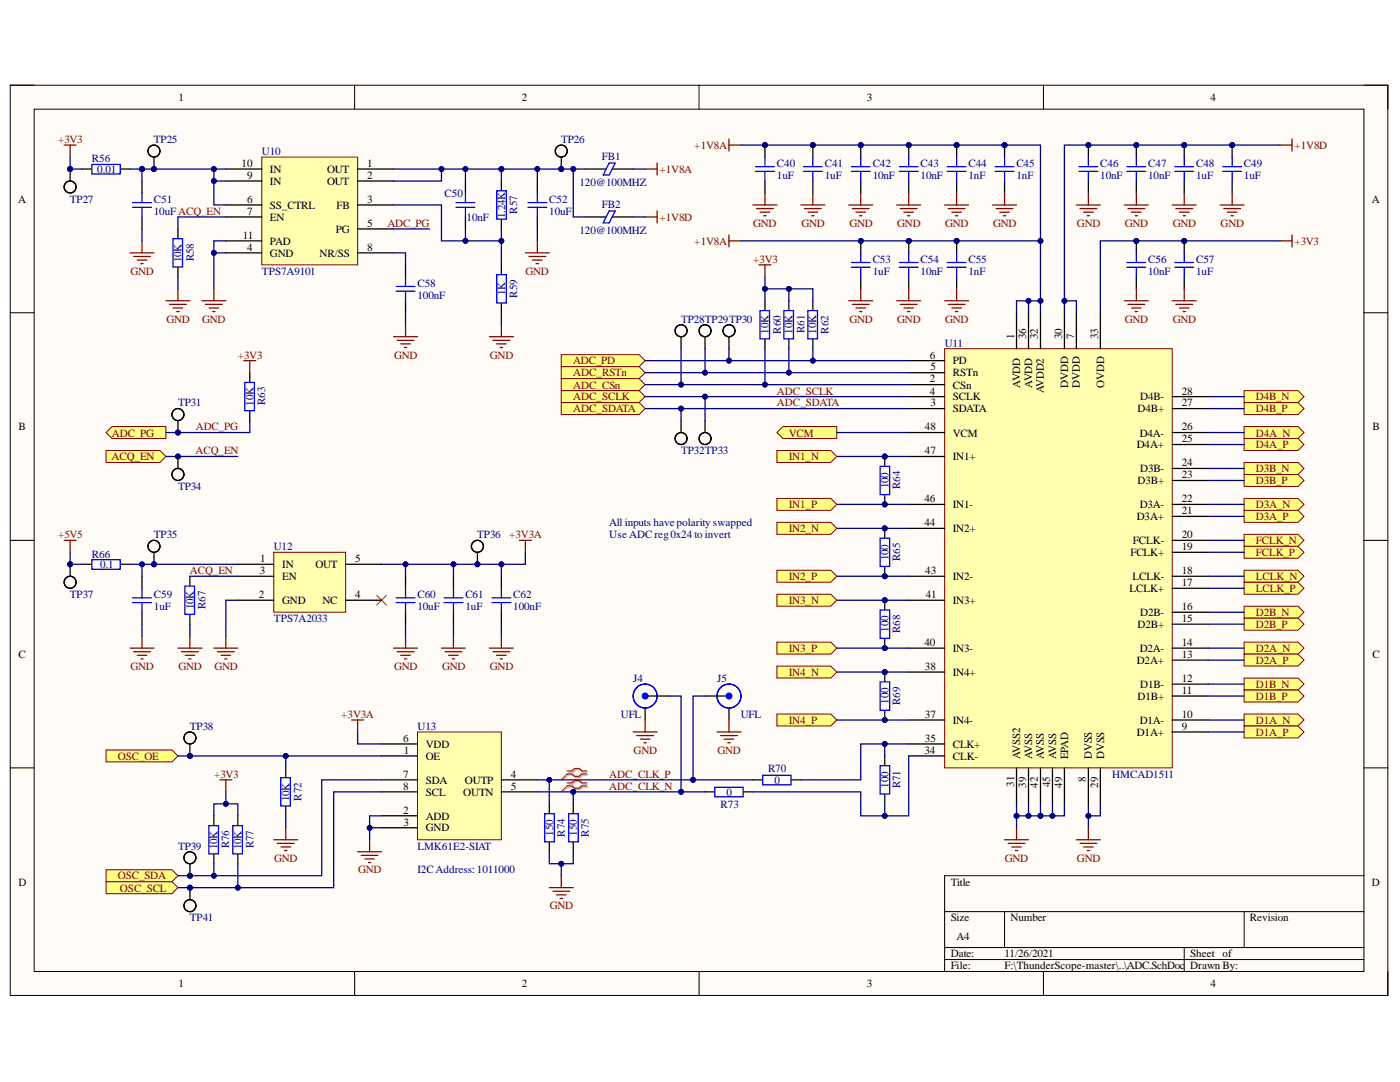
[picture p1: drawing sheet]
<svg xmlns="http://www.w3.org/2000/svg" width="279mm" height="216mm" viewBox="0 0 279 216" stroke-linecap="round" stroke-linejoin="round" font-family="sans-serif">
<defs><g id="words">
<g font-size="2.2">
<text x="35.6" y="20.1">1</text>
<text x="104.1" y="20.1">2</text>
<text x="173" y="20.1">3</text>
<text x="241.6" y="20.1">4</text>
<text x="48.2" y="33.3">10</text>
<text x="49.3" y="35.7">9</text>
<text x="53.9" y="34.5">IN</text>
<text x="65.3" y="34.5">OUT</text>
<text x="73.3" y="33.3">1</text>
<text x="73.3" y="35.7">2</text>
<text x="3.6" y="40.4">A</text>
<text x="49.3" y="40.4">6</text>
<text x="53.9" y="41.7">SS_CTRL</text>
<text x="53.9" y="36.9">IN</text>
<text x="65.3" y="36.9">OUT</text>
<text x="67.2" y="41.7">FB</text>
<text x="73.3" y="40.4">3</text>
<text x="273.8" y="40.4">A</text>
<text x="48.5" y="47.6">11</text>
<text x="49.3" y="42.9">7</text>
<text x="53.9" y="44.1">EN</text>
<text x="67" y="46.4">PG</text>
<text x="73.3" y="45.2">5</text>
<text x="49.3" y="50.1">4</text>
<text x="53.9" y="51.2">GND</text>
<text x="53.9" y="48.8">PAD</text>
<text x="63.8" y="51.2">NR/SS</text>
<text x="73.3" y="50.1">8</text>
<text x="185.6" y="71.5">6</text>
<text x="202.4" y="67.7" transform="rotate(-90 202.4 67.7)">1</text>
<text x="204.8" y="67.7" transform="rotate(-90 204.8 67.7)">36</text>
<text x="207.2" y="67.7" transform="rotate(-90 207.2 67.7)">32</text>
<text x="212" y="67.7" transform="rotate(-90 212 67.7)">30</text>
<text x="214.3" y="67.7" transform="rotate(-90 214.3 67.7)">7</text>
<text x="219.2" y="67.7" transform="rotate(-90 219.2 67.7)">33</text>
<text x="185.6" y="76.3">2</text>
<text x="185.7" y="73.9">5</text>
<text x="190.2" y="72.7">PD</text>
<text x="190.2" y="75.1">RSTn</text>
<text x="190.2" y="77.5">CSn</text>
<text x="203.6" y="77.4" transform="rotate(-90 203.6 77.4)">AVDD</text>
<text x="206" y="77.4" transform="rotate(-90 206 77.4)">AVDD</text>
<text x="213.2" y="77.4" transform="rotate(-90 213.2 77.4)">DVDD</text>
<text x="215.5" y="77.4" transform="rotate(-90 215.5 77.4)">DVDD</text>
<text x="220.3" y="77.4" transform="rotate(-90 220.3 77.4)">OVDD</text>
<text x="185.6" y="78.7">4</text>
<text x="185.7" y="81.1">3</text>
<text x="190.2" y="79.9">SCLK</text>
<text x="190.2" y="82.3">SDATA</text>
<text x="208.3" y="78.5" transform="rotate(-90 208.3 78.5)">AVDD2</text>
<text x="227" y="82.3">D4B+</text>
<text x="227.5" y="79.9">D4B-</text>
<text x="235.8" y="81.1">27</text>
<text x="235.8" y="78.7">28</text>
<text x="3.7" y="85.8">B</text>
<text x="184.6" y="85.8">48</text>
<text x="190.2" y="87.1">VCM</text>
<text x="226.9" y="89.5">D4A+</text>
<text x="227.5" y="87.1">D4A-</text>
<text x="235.8" y="88.3">25</text>
<text x="235.8" y="85.8">26</text>
<text x="273.9" y="85.8">B</text>
<text x="184.6" y="90.7">47</text>
<text x="190.2" y="91.8">IN1+</text>
<text x="227.5" y="94.2">D3B-</text>
<text x="235.8" y="95.5">23</text>
<text x="235.8" y="93">24</text>
<text x="184.5" y="100.2">46</text>
<text x="190.2" y="101.4">IN1-</text>
<text x="227" y="96.7">D3B+</text>
<text x="227.5" y="101.4">D3A-</text>
<text x="235.8" y="100.2">22</text>
<text x="184.5" y="105">44</text>
<text x="190.2" y="106.2">IN2+</text>
<text x="226.9" y="103.8">D3A+</text>
<text x="235.8" y="107.4">20</text>
<text x="235.8" y="102.6">21</text>
<text x="51.9" y="112.1">1</text>
<text x="56.3" y="113.4">IN</text>
<text x="62.9" y="113.4">OUT</text>
<text x="70.9" y="112.1">5</text>
<text x="225.6" y="110.9">FCLK+</text>
<text x="226.1" y="108.6">FCLK-</text>
<text x="235.8" y="109.8">19</text>
<text x="51.7" y="119.3">2</text>
<text x="51.9" y="114.6">3</text>
<text x="56.3" y="115.8">EN</text>
<text x="70.9" y="119.3">4</text>
<text x="184.7" y="114.6">43</text>
<text x="184.7" y="119.3">41</text>
<text x="190.2" y="115.8">IN2-</text>
<text x="225.4" y="118.1">LCLK+</text>
<text x="226" y="115.8">LCLK-</text>
<text x="235.8" y="116.9">17</text>
<text x="235.8" y="114.6">18</text>
<text x="56.3" y="120.5">GND</text>
<text x="64.4" y="120.5">NC</text>
<text x="190.2" y="120.5">IN3+</text>
<text x="227" y="125.3">D2B+</text>
<text x="227.5" y="123">D2B-</text>
<text x="235.8" y="124.1">15</text>
<text x="235.8" y="121.7">16</text>
<text x="3.7" y="131.3">C</text>
<text x="184.5" y="128.9">40</text>
<text x="190.2" y="130.1">IN3-</text>
<text x="227.5" y="130.1">D2A-</text>
<text x="235.8" y="131.3">13</text>
<text x="235.8" y="128.9">14</text>
<text x="273.9" y="131.3">C</text>
<text x="184.6" y="133.7">38</text>
<text x="190.2" y="134.9">IN4+</text>
<text x="226.9" y="132.5">D2A+</text>
<text x="227.5" y="137.2">D1B-</text>
<text x="235.8" y="136.1">12</text>
<text x="184.6" y="143.2">37</text>
<text x="227" y="139.6">D1B+</text>
<text x="235.8" y="143.2">10</text>
<text x="235.8" y="138.4">11</text>
<text x="80.4" y="148">6</text>
<text x="85" y="149.2">VDD</text>
<text x="184.6" y="148">35</text>
<text x="190.2" y="144.4">IN4-</text>
<text x="190.2" y="149.2">CLK+</text>
<text x="226.9" y="146.8">D1A+</text>
<text x="227.5" y="144.4">D1A-</text>
<text x="235.8" y="145.6">9</text>
<text x="80.4" y="155.2">7</text>
<text x="80.6" y="150.4">1</text>
<text x="85" y="151.6">OE</text>
<text x="101.9" y="155.2">4</text>
<text x="184.5" y="150.4">34</text>
<text x="190.2" y="151.6">CLK-</text>
<text x="203.6" y="151.5" transform="rotate(-90 203.6 151.5)">AVSS2</text>
<text x="206" y="151.5" transform="rotate(-90 206 151.5)">AVSS</text>
<text x="208.3" y="151.5" transform="rotate(-90 208.3 151.5)">AVSS</text>
<text x="210.8" y="151.5" transform="rotate(-90 210.8 151.5)">AVSS</text>
<text x="213.2" y="151.5" transform="rotate(-90 213.2 151.5)">EPAD</text>
<text x="217.9" y="151.5" transform="rotate(-90 217.9 151.5)">DVSS</text>
<text x="220.3" y="151.5" transform="rotate(-90 220.3 151.5)">DVSS</text>
<text x="80.4" y="157.5">8</text>
<text x="85" y="156.4">SDA</text>
<text x="85" y="158.8">SCL</text>
<text x="92.5" y="158.8">OUTN</text>
<text x="92.8" y="156.4">OUTP</text>
<text x="101.9" y="157.5">5</text>
<text x="202.4" y="157" transform="rotate(-90 202.4 157)">31</text>
<text x="204.8" y="157.2" transform="rotate(-90 204.8 157.2)">39</text>
<text x="207.2" y="157.2" transform="rotate(-90 207.2 157.2)">42</text>
<text x="209.6" y="157.1" transform="rotate(-90 209.6 157.1)">45</text>
<text x="212" y="157.2" transform="rotate(-90 212 157.2)">49</text>
<text x="216.7" y="156.1" transform="rotate(-90 216.7 156.1)">8</text>
<text x="219.2" y="157.2" transform="rotate(-90 219.2 157.2)">29</text>
<text x="80.4" y="162.4">2</text>
<text x="80.5" y="164.7">3</text>
<text x="85" y="163.5">ADD</text>
<text x="85" y="165.9">GND</text>
<text x="3.7" y="176.7">D</text>
<text x="189.7" y="176.7">Title</text>
<text x="273.8" y="176.7">D</text>
<text x="189.7" y="183.8">Size</text>
<text x="201.7" y="183.8">Number</text>
<text x="249.4" y="183.8">Revision</text>
<text x="189.7" y="191">Date:</text>
<text x="190.9" y="187.5">A4</text>
<text x="200.5" y="191">11/26/2021</text>
<text x="237.5" y="191">Sheet of</text>
<text x="35.6" y="197">1</text>
<text x="104.1" y="197">2</text>
<text x="173" y="197">3</text>
<text x="189.7" y="193.4">File:</text>
<text x="200.5" y="193.4">F:\ThunderScope-master\..\ADC.SchDoc</text>
<text x="237.5" y="193.4">Drawn By:</text>
<text x="241.6" y="197">4</text>
</g>
<g font-size="2.2" fill="#800000">
<text x="11.6" y="28.5">+3V3</text>
<text x="138.6" y="29.7">+1V8A</text>
<text x="258.3" y="29.7">+1V8D</text>
<text x="131.6" y="34.5">+1V8A</text>
<text x="77.3" y="45.2">ADC_PG</text>
<text x="131.6" y="44.1">+1V8D</text>
<text x="150.3" y="45.2">GND</text>
<text x="160" y="45.2">GND</text>
<text x="169.5" y="45.2">GND</text>
<text x="179.1" y="45.2">GND</text>
<text x="188.6" y="45.2">GND</text>
<text x="198.2" y="45.2">GND</text>
<text x="214.9" y="45.2">GND</text>
<text x="224.5" y="45.2">GND</text>
<text x="234.1" y="45.2">GND</text>
<text x="243.6" y="45.2">GND</text>
<text x="138.6" y="48.8">+1V8A</text>
<text x="150.3" y="52.4">+3V3</text>
<text x="258.3" y="48.8">+3V3</text>
<text x="26.1" y="54.8">GND</text>
<text x="104.9" y="54.8">GND</text>
<text x="33.2" y="64.4">GND</text>
<text x="40.3" y="64.4">GND</text>
<text x="169.5" y="64.4">GND</text>
<text x="179.1" y="64.4">GND</text>
<text x="188.6" y="64.4">GND</text>
<text x="224.5" y="64.4">GND</text>
<text x="234.1" y="64.4">GND</text>
<text x="47.5" y="71.5">+3V3</text>
<text x="78.7" y="71.5">GND</text>
<text x="97.8" y="71.5">GND</text>
<text x="114.4" y="72.7">ADC_PD</text>
<text x="114.4" y="75.1">ADC_RSTn</text>
<text x="114.4" y="77.5">ADC_CSn</text>
<text x="114.4" y="79.9">ADC_SCLK</text>
<text x="114.4" y="82.3">ADC_SDATA</text>
<text x="155" y="78.7">ADC_SCLK</text>
<text x="155" y="81.1">ADC_SDATA</text>
<text x="250.6" y="79.9">D4B_N</text>
<text x="250.6" y="82.3">D4B_P</text>
<text x="22.3" y="87.1">ADC_PG</text>
<text x="39.1" y="85.8">ADC_PG</text>
<text x="157.4" y="87.1">VCM</text>
<text x="250.6" y="87.1">D4A_N</text>
<text x="250.6" y="89.5">D4A_P</text>
<text x="22.2" y="91.8">ACQ_EN</text>
<text x="39" y="90.7">ACQ_EN</text>
<text x="157.4" y="91.8">IN1_N</text>
<text x="250.6" y="94.2">D3B_N</text>
<text x="157.4" y="101.4">IN1_P</text>
<text x="250.6" y="96.7">D3B_P</text>
<text x="250.6" y="101.4">D3A_N</text>
<text x="11.6" y="107.4">+5V5</text>
<text x="101.6" y="107.4">+3V3A</text>
<text x="157.4" y="106.2">IN2_N</text>
<text x="250.6" y="103.8">D3A_P</text>
<text x="250.6" y="108.6">FCLK_N</text>
<text x="250.6" y="110.9">FCLK_P</text>
<text x="37.9" y="114.6">ACQ_EN</text>
<text x="157.4" y="115.8">IN2_P</text>
<text x="250.6" y="115.8">LCLK_N</text>
<text x="250.6" y="118.1">LCLK_P</text>
<text x="157.4" y="120.5">IN3_N</text>
<text x="250.6" y="123">D2B_N</text>
<text x="250.6" y="125.3">D2B_P</text>
<text x="157.4" y="130.1">IN3_P</text>
<text x="250.6" y="130.1">D2A_N</text>
<text x="26.1" y="133.7">GND</text>
<text x="35.6" y="133.7">GND</text>
<text x="42.8" y="133.7">GND</text>
<text x="78.7" y="133.7">GND</text>
<text x="88.2" y="133.7">GND</text>
<text x="97.8" y="133.7">GND</text>
<text x="157.4" y="134.9">IN4_N</text>
<text x="250.6" y="132.5">D2A_P</text>
<text x="250.6" y="137.2">D1B_N</text>
<text x="68.1" y="143.2">+3V3A</text>
<text x="250.6" y="139.6">D1B_P</text>
<text x="157.4" y="144.4">IN4_P</text>
<text x="250.6" y="144.4">D1A_N</text>
<text x="250.6" y="146.8">D1A_P</text>
<text x="23.5" y="151.6">OSC_OE</text>
<text x="42.7" y="155.2">+3V3</text>
<text x="121.6" y="155.2">ADC_CLK_P</text>
<text x="126.5" y="150.4">GND</text>
<text x="143.2" y="150.4">GND</text>
<text x="121.6" y="157.5">ADC_CLK_N</text>
<text x="54.7" y="171.9">GND</text>
<text x="200.6" y="171.9">GND</text>
<text x="214.9" y="171.9">GND</text>
<text x="23.5" y="175.5">OSC_SDA</text>
<text x="23.9" y="177.9">OSC_SCL</text>
<text x="71.5" y="174.3">GND</text>
<text x="109.7" y="181.5">GND</text>
</g>
<g font-size="2.2" fill="#000080">
<text x="30.7" y="28.5">TP25</text>
<text x="112" y="28.5">TP26</text>
<text x="18.4" y="32.4">R56</text>
<text x="19.4" y="34.5">0.01</text>
<text x="52.3" y="30.9">U10</text>
<text x="120.1" y="31.9">FB1</text>
<text x="155" y="33.3">C40</text>
<text x="155" y="35.7">1uF</text>
<text x="164.6" y="33.3">C41</text>
<text x="164.6" y="35.7">1uF</text>
<text x="174.2" y="33.3">C42</text>
<text x="174.2" y="35.7">10nF</text>
<text x="183.7" y="33.3">C43</text>
<text x="183.7" y="35.7">10nF</text>
<text x="193.3" y="33.3">C44</text>
<text x="193.3" y="35.7">1nF</text>
<text x="202.8" y="33.3">C45</text>
<text x="202.8" y="35.7">1nF</text>
<text x="219.6" y="33.3">C46</text>
<text x="219.6" y="35.7">10nF</text>
<text x="229.1" y="33.3">C47</text>
<text x="229.1" y="35.7">10nF</text>
<text x="238.7" y="33.3">C48</text>
<text x="238.7" y="35.7">1uF</text>
<text x="248.3" y="33.3">C49</text>
<text x="248.3" y="35.7">1uF</text>
<text x="14" y="40.4">TP27</text>
<text x="30.7" y="40.4">C51</text>
<text x="88.7" y="39.2">C50</text>
<text x="109.6" y="40.4">C52</text>
<text x="115.6" y="37.1">120@100MHZ</text>
<text x="120.1" y="41.4">FB2</text>
<text x="30.7" y="42.9">10uFACQ_EN</text>
<text x="93.1" y="44.1">10nF</text>
<text x="100.8" y="43.6" transform="rotate(-90 100.8 43.6)">1.24K</text>
<text x="103.2" y="42.6" transform="rotate(-90 103.2 42.6)">R57</text>
<text x="109.6" y="42.9">10uF</text>
<text x="115.6" y="46.7">120@100MHZ</text>
<text x="36.2" y="52.3" transform="rotate(-90 36.2 52.3)">10K</text>
<text x="38.7" y="52.2" transform="rotate(-90 38.7 52.2)">R58</text>
<text x="174.2" y="52.4">C53</text>
<text x="183.7" y="52.4">C54</text>
<text x="193.3" y="52.4">C55</text>
<text x="229.1" y="52.4">C56</text>
<text x="238.7" y="52.4">C57</text>
<text x="52.3" y="54.8">TPS7A9101</text>
<text x="83.3" y="57.2">C58</text>
<text x="83.3" y="59.6">100nF</text>
<text x="100.8" y="58.9" transform="rotate(-90 100.8 58.9)">1K</text>
<text x="103.2" y="59.4" transform="rotate(-90 103.2 59.4)">R59</text>
<text x="174.2" y="54.8">1uF</text>
<text x="183.7" y="54.8">10nF</text>
<text x="193.3" y="54.8">1nF</text>
<text x="229.1" y="54.8">10nF</text>
<text x="238.7" y="54.8">1uF</text>
<text x="135.9" y="64.4">TP28TP29TP30</text>
<text x="153.4" y="66.6" transform="rotate(-90 153.4 66.6)">10K</text>
<text x="155.8" y="66.6" transform="rotate(-90 155.8 66.6)">R60</text>
<text x="158.2" y="66.6" transform="rotate(-90 158.2 66.6)">10K</text>
<text x="160.5" y="66.5" transform="rotate(-90 160.5 66.5)">R61</text>
<text x="162.9" y="66.6" transform="rotate(-90 162.9 66.6)">10K</text>
<text x="165.4" y="66.6" transform="rotate(-90 165.4 66.6)">R62</text>
<text x="188.5" y="69.2">U11</text>
<text x="35.5" y="81.1">TP31</text>
<text x="50.6" y="81" transform="rotate(-90 50.6 81)">10K</text>
<text x="53" y="80.8" transform="rotate(-90 53 80.8)">R63</text>
<text x="135.9" y="90.7">TP32TP33</text>
<text x="35.5" y="97.8">TP34</text>
<text x="177.3" y="97.4" transform="rotate(-90 177.3 97.4)">100</text>
<text x="179.7" y="97.6" transform="rotate(-90 179.7 97.6)">R64</text>
<text x="30.7" y="107.4">TP35</text>
<text x="95.2" y="107.4">TP36</text>
<text x="121.6" y="105">All inputs havepolarity swapped</text>
<text x="121.6" y="107.4">Use ADCreg0x24 to invert</text>
<text x="18.4" y="111.3">R66</text>
<text x="20" y="113.4">0.1</text>
<text x="54.6" y="109.8">U12</text>
<text x="177.3" y="111.8" transform="rotate(-90 177.3 111.8)">100</text>
<text x="179.7" y="112" transform="rotate(-90 179.7 112)">R65</text>
<text x="14" y="119.3">TP37</text>
<text x="30.7" y="119.3">C59</text>
<text x="83.3" y="119.3">C60</text>
<text x="92.9" y="119.3">C61</text>
<text x="102.4" y="119.3">C62</text>
<text x="30.7" y="121.7">1uF</text>
<text x="38.7" y="121.6" transform="rotate(-90 38.7 121.6)">10K</text>
<text x="41" y="121.5" transform="rotate(-90 41 121.5)">R67</text>
<text x="54.6" y="124.1">TPS7A2033</text>
<text x="83.3" y="121.7">10uF</text>
<text x="92.9" y="121.7">1uF</text>
<text x="102.4" y="121.7">100nF</text>
<text x="177.3" y="126.1" transform="rotate(-90 177.3 126.1)">100</text>
<text x="179.7" y="126.3" transform="rotate(-90 179.7 126.3)">R68</text>
<text x="126.4" y="136.1">J4</text>
<text x="143.1" y="136.1">J5</text>
<text x="123.9" y="143.2">UFL</text>
<text x="147.9" y="143.2">UFL</text>
<text x="177.3" y="140.5" transform="rotate(-90 177.3 140.5)">100</text>
<text x="179.7" y="140.6" transform="rotate(-90 179.7 140.6)">R69</text>
<text x="37.9" y="145.6">TP38</text>
<text x="83.3" y="145.6">U13</text>
<text x="153.3" y="154">R70</text>
<text x="222" y="155.2">HMCAD1511</text>
<text x="57.8" y="159.9" transform="rotate(-90 57.8 159.9)">10K</text>
<text x="60.1" y="159.7" transform="rotate(-90 60.1 159.7)">R72</text>
<text x="143.8" y="161.2">R73</text>
<text x="145" y="158.8">0</text>
<text x="154.5" y="156.4">0</text>
<text x="177.3" y="157.2" transform="rotate(-90 177.3 157.2)">100</text>
<text x="179.7" y="157.3" transform="rotate(-90 179.7 157.3)">R71</text>
<text x="110.4" y="166.8" transform="rotate(-90 110.4 166.8)">150</text>
<text x="112.8" y="166.9" transform="rotate(-90 112.8 166.9)">R74</text>
<text x="115.1" y="166.8" transform="rotate(-90 115.1 166.8)">150</text>
<text x="117.5" y="166.9" transform="rotate(-90 117.5 166.9)">R75</text>
<text x="35.5" y="169.5">TP39</text>
<text x="43.4" y="169.5" transform="rotate(-90 43.4 169.5)">10K</text>
<text x="45.8" y="169.3" transform="rotate(-90 45.8 169.3)">R76</text>
<text x="48.2" y="169.5" transform="rotate(-90 48.2 169.5)">10K</text>
<text x="50.6" y="169.3" transform="rotate(-90 50.6 169.3)">R77</text>
<text x="83.3" y="169.5">LMK61E2-SIAT</text>
<text x="83.3" y="174.3">I2CAddress: 1011000</text>
<text x="37.9" y="183.8">TP41</text>
</g>
</g></defs>
<path d="M2 17h275v181.6h-275z" fill-rule="evenodd" fill="#fffcf8"/>
<path d="M2 17h275v181.6h-275z" fill="none" stroke="#000" stroke-width=".2"/>
<path d="M6.8 21.8h265.4v172.1h-265.4z" fill-rule="evenodd" fill="#fffcf8"/>
<g fill="none" stroke="#000" stroke-width=".2">
<path d="M2 17h4.8M70.8 17v4.8M139.5 17v4.8M208.2 17v4.8M272.2 17h4.8v4.8M6.8 21.8h265.4v172.1h-265.4zM2 62.4h4.8M272.2 62.4h4.8M2 107.8h4.8M272.2 107.8h4.8M2 153.2h4.8M272.2 153.2h4.8"/>
<path d="M272.2 174.7h-83.7v19.2M70.8 193.9v4.7M139.5 193.9v4.7M188.5 181.9h83.7M188.5 189.1h83.7M188.5 191.5h83.7M200.5 181.9v7.2M208.2 193.9v4.7M236.3 189.1v4.8M248.3 181.9v7.2M277 193.9v4.7"/>
</g>
<path d="M52.2 31.3h19.2v21.6h-19.2z" fill-rule="evenodd" fill="#ffffb0"/>
<path d="M52.2 31.3h19.2v21.6h-19.2z" fill="none" stroke="#800000" stroke-width=".2"/>
<g fill="none" stroke="#000" stroke-width=".25">
<path d="M28.3 36.1v2.4M45.1 33.7h7.1M45.1 36.1h7.1M71.4 33.7h7.1M71.4 36.1h7.1M92.9 36.1v2.4M100.1 36.1v1.9M107.2 36.1v2.4M28.3 43.3v2.4M45.1 40.9h7.1M45.1 50.5h7.1M45.1 43.3h7.1"/>
<path d="M45.1 48.1h7.1M71.4 40.9h7.1M71.4 50.5h7.1M71.4 45.7h7.1M80.9 52.9v2.3M92.9 43.3v2.4M100.1 43.8v1.9M100.1 52.9v1.8M107.2 43.3v2.4M80.9 60v2.4M100.1 60.5v1.9"/>
</g>
<g fill="none" stroke="#800000" stroke-width=".25">
<path d="M12.8 28.9h2.4M14 28.9v2.4M25.9 50.5h4.8M26.7 51.2h3.3M27.4 51.9h1.9M28.1 52.6h.5M28.3 48.1v2.4M42.7 57.6v2.4M104.8 50.5h4.8M105.6 51.2h3.3M106.3 51.9h1.9M107 52.6h.5"/>
<path d="M107.2 48.1v2.4M40.3 60h4.8M41 60.7h3.4M41.7 61.5h1.9M42.4 62.2h.5M78.5 67.2h4.8M79.3 67.9h3.3M80 68.6h1.9M80.7 69.3h.5M80.9 64.8v2.4M97.7 67.2h4.8M98.4 67.9h3.3"/>
<path d="M99.1 68.6h1.9M99.8 69.3h.5M100.1 64.8v2.4"/>
</g>
<g fill="none" stroke="#00f" stroke-width=".25">
<path d="M28.3 38.5v1.9M92.9 38.5v1.9M99.1 38.1h2v5.6h-2zM107.2 38.5v1.9M26.5 41.4h3.7M26.5 40.4h3.7M28.3 41.4v1.9M79.1 58.1h3.7M79.1 57.2h3.7M80.9 55.2v2M80.9 58.1v1.9M91 41.4h3.8"/>
<path d="M91 40.4h3.8M92.9 41.4v1.9M99.1 54.8h2v5.6h-2zM105.4 41.4h3.7M105.4 40.4h3.7M107.2 41.4v1.9"/>
</g>
<circle cx="226.8" cy="48.1" r=".48" fill="#000080"/>
<circle cx="226.8" cy="48.1" r=".48" fill="none" stroke="#000080" stroke-width=".2"/>
<path d="M226.8 48.1v2.4M226.8 55.2v2.4" fill="none" stroke="#000" stroke-width=".25"/>
<circle cx="226.8" cy="48.1" r=".48" fill="#000080"/>
<circle cx="226.8" cy="48.1" r=".48" fill="none" stroke="#000080" stroke-width=".2"/>
<path d="M224.9 53.3h3.8M224.9 52.4h3.8M226.8 50.5v1.9M226.8 53.3v1.9" fill="none" stroke="#00f" stroke-width=".25"/>
<circle cx="236.3" cy="48.1" r=".48" fill="#000080"/>
<circle cx="236.3" cy="48.1" r=".48" fill="none" stroke="#000080" stroke-width=".2"/>
<path d="M236.3 48.1v2.4M236.3 55.2v2.4" fill="none" stroke="#000" stroke-width=".25"/>
<circle cx="236.3" cy="48.1" r=".48" fill="#000080"/>
<circle cx="236.3" cy="48.1" r=".48" fill="none" stroke="#000080" stroke-width=".2"/>
<path d="M234.5 53.3h3.7M234.5 52.4h3.7M236.3 50.5v1.9M236.3 53.3v1.9" fill="none" stroke="#00f" stroke-width=".25"/>
<path d="M226.8 57.6v2.4M236.3 57.6v2.4M255.5 48.1h2.4M257.9 46.9v2.4M224.4 60h4.8M225.1 60.7h3.3M225.8 61.5h1.9M226.5 62.2h.5M233.9 60h4.8M234.7 60.7h3.3M235.4 61.5h1.9M236.1 62.2h.5" fill="none" stroke="#800000" stroke-width=".25"/>
<circle cx="217.2" cy="29" r=".48" fill="#000080"/>
<circle cx="217.2" cy="29" r=".48" fill="none" stroke="#000080" stroke-width=".2"/>
<path d="M217.2 28.9v2.4M217.2 36.1v2.4" fill="none" stroke="#000" stroke-width=".25"/>
<circle cx="217.2" cy="29" r=".48" fill="#000080"/>
<circle cx="217.2" cy="29" r=".48" fill="none" stroke="#000080" stroke-width=".2"/>
<path d="M215.3 34.2h3.8M215.3 33.3h3.8M217.2 31.3v2M217.2 34.2v1.9" fill="none" stroke="#00f" stroke-width=".25"/>
<circle cx="245.9" cy="29" r=".48" fill="#000080"/>
<circle cx="245.9" cy="29" r=".48" fill="none" stroke="#000080" stroke-width=".2"/>
<path d="M245.9 28.9v2.4M245.9 36.1v2.4" fill="none" stroke="#000" stroke-width=".25"/>
<circle cx="245.9" cy="29" r=".48" fill="#000080"/>
<circle cx="245.9" cy="29" r=".48" fill="none" stroke="#000080" stroke-width=".2"/>
<path d="M244 34.2h3.8M244 33.3h3.8M245.9 31.3v2M245.9 34.2v1.9" fill="none" stroke="#00f" stroke-width=".25"/>
<path d="M217.2 38.5v2.4M245.9 38.5v2.4M214.8 40.9h4.8M215.5 41.6h3.4M216.3 42.3h1.9M217 43h.5M243.5 40.9h4.8M244.2 41.6h3.4M244.9 42.3h2M245.7 43h.4" fill="none" stroke="#800000" stroke-width=".25"/>
<circle cx="226.8" cy="29" r=".48" fill="#000080"/>
<circle cx="226.8" cy="29" r=".48" fill="none" stroke="#000080" stroke-width=".2"/>
<path d="M226.8 28.9v2.4M226.8 36.1v2.4" fill="none" stroke="#000" stroke-width=".25"/>
<circle cx="226.8" cy="29" r=".48" fill="#000080"/>
<circle cx="226.8" cy="29" r=".48" fill="none" stroke="#000080" stroke-width=".2"/>
<path d="M224.9 34.2h3.8M224.9 33.3h3.8M226.8 31.3v2M226.8 34.2v1.9" fill="none" stroke="#00f" stroke-width=".25"/>
<circle cx="236.3" cy="29" r=".48" fill="#000080"/>
<circle cx="236.3" cy="29" r=".48" fill="none" stroke="#000080" stroke-width=".2"/>
<path d="M236.3 28.9v2.4M236.3 36.1v2.4" fill="none" stroke="#000" stroke-width=".25"/>
<circle cx="236.3" cy="29" r=".48" fill="#000080"/>
<circle cx="236.3" cy="29" r=".48" fill="none" stroke="#000080" stroke-width=".2"/>
<path d="M234.5 34.2h3.7M234.5 33.3h3.7M236.3 31.3v2M236.3 34.2v1.9" fill="none" stroke="#00f" stroke-width=".25"/>
<path d="M226.8 38.5v2.4M236.3 38.5v2.4M255.5 28.9h2.4M257.9 27.8v2.3M224.4 40.9h4.8M225.1 41.6h3.3M225.8 42.3h1.9M226.5 43h.5M233.9 40.9h4.8M234.7 41.6h3.3M235.4 42.3h1.9M236.1 43h.5" fill="none" stroke="#800000" stroke-width=".25"/>
<circle cx="181.3" cy="29" r=".48" fill="#000080"/>
<circle cx="181.3" cy="29" r=".48" fill="none" stroke="#000080" stroke-width=".2"/>
<path d="M181.4 28.9v2.4M181.4 36.1v2.4" fill="none" stroke="#000" stroke-width=".25"/>
<circle cx="181.3" cy="29" r=".48" fill="#000080"/>
<circle cx="181.3" cy="29" r=".48" fill="none" stroke="#000080" stroke-width=".2"/>
<path d="M179.5 34.2h3.7M179.5 33.3h3.7M181.4 31.3v2M181.4 34.2v1.9" fill="none" stroke="#00f" stroke-width=".25"/>
<circle cx="152.7" cy="28.9" r=".48" fill="#000080"/>
<circle cx="152.7" cy="28.9" r=".48" fill="none" stroke="#000080" stroke-width=".2"/>
<path d="M152.7 28.9v2.4M152.7 36.1v2.4" fill="none" stroke="#000" stroke-width=".25"/>
<circle cx="152.7" cy="28.9" r=".48" fill="#000080"/>
<circle cx="152.7" cy="28.9" r=".48" fill="none" stroke="#000080" stroke-width=".2"/>
<path d="M150.8 34.2h3.7M150.8 33.3h3.7M152.7 31.3v2M152.7 34.2v1.9" fill="none" stroke="#00f" stroke-width=".25"/>
<path d="M152.7 38.5v2.4M181.4 38.5v2.4M150.3 40.9h4.7M151 41.6h3.3M151.7 42.3h1.9M152.4 43h.5M179 40.9h4.7M179.7 41.6h3.3M180.4 42.3h1.9M181.1 43h.5" fill="none" stroke="#800000" stroke-width=".25"/>
<circle cx="171.8" cy="28.9" r=".48" fill="#000080"/>
<circle cx="171.8" cy="28.9" r=".48" fill="none" stroke="#000080" stroke-width=".2"/>
<path d="M171.8 28.9v2.4M171.8 36.1v2.4" fill="none" stroke="#000" stroke-width=".25"/>
<circle cx="171.8" cy="28.9" r=".48" fill="#000080"/>
<circle cx="171.8" cy="28.9" r=".48" fill="none" stroke="#000080" stroke-width=".2"/>
<path d="M169.9 34.2h3.8M169.9 33.3h3.8M171.8 31.3v2M171.8 34.2v1.9" fill="none" stroke="#00f" stroke-width=".25"/>
<circle cx="162.2" cy="28.9" r=".48" fill="#000080"/>
<circle cx="162.2" cy="28.9" r=".48" fill="none" stroke="#000080" stroke-width=".2"/>
<path d="M162.2 28.9v2.4M162.2 36.1v2.4" fill="none" stroke="#000" stroke-width=".25"/>
<circle cx="162.2" cy="28.9" r=".48" fill="#000080"/>
<circle cx="162.2" cy="28.9" r=".48" fill="none" stroke="#000080" stroke-width=".2"/>
<path d="M160.3 34.2h3.8M160.3 33.3h3.8M162.2 31.3v2M162.2 34.2v1.9" fill="none" stroke="#00f" stroke-width=".25"/>
<path d="M162.2 38.5v2.4M171.8 38.5v2.4M159.8 40.9h4.8M160.5 41.6h3.4M161.3 42.3h1.9M162 43h.5M169.4 40.9h4.8M170.1 41.6h3.4M170.8 42.3h1.9M171.5 43h.5" fill="none" stroke="#800000" stroke-width=".25"/>
<circle cx="190.9" cy="29" r=".48" fill="#000080"/>
<circle cx="190.9" cy="29" r=".48" fill="none" stroke="#000080" stroke-width=".2"/>
<path d="M190.9 28.9v2.4M190.9 36.1v2.4" fill="none" stroke="#000" stroke-width=".25"/>
<circle cx="190.9" cy="29" r=".48" fill="#000080"/>
<circle cx="190.9" cy="29" r=".48" fill="none" stroke="#000080" stroke-width=".2"/>
<path d="M189 34.2h3.8M189 33.3h3.8M190.9 31.3v2M190.9 34.2v1.9" fill="none" stroke="#00f" stroke-width=".25"/>
<path d="M190.9 38.5v2.4M188.5 40.9h4.8M189.2 41.6h3.4M190 42.3h1.9M190.7 43h.5" fill="none" stroke="#800000" stroke-width=".25"/>
<circle cx="200.5" cy="29" r=".48" fill="#000080"/>
<circle cx="200.5" cy="29" r=".48" fill="none" stroke="#000080" stroke-width=".2"/>
<path d="M200.5 28.9v2.4M200.5 36.1v2.4" fill="none" stroke="#000" stroke-width=".25"/>
<circle cx="200.5" cy="29" r=".48" fill="#000080"/>
<circle cx="200.5" cy="29" r=".48" fill="none" stroke="#000080" stroke-width=".2"/>
<path d="M198.6 34.2h3.8M198.6 33.3h3.8M200.5 31.3v2M200.5 34.2v1.9" fill="none" stroke="#00f" stroke-width=".25"/>
<path d="M200.5 38.5v2.4M198.1 40.9h4.8M198.8 41.6h3.4M199.5 42.3h1.9M200.2 43h.5" fill="none" stroke="#800000" stroke-width=".25"/>
<circle cx="171.8" cy="48.1" r=".48" fill="#000080"/>
<circle cx="171.8" cy="48.1" r=".48" fill="none" stroke="#000080" stroke-width=".2"/>
<path d="M171.8 48.1v2.4M171.8 55.2v2.4" fill="none" stroke="#000" stroke-width=".25"/>
<circle cx="171.8" cy="48.1" r=".48" fill="#000080"/>
<circle cx="171.8" cy="48.1" r=".48" fill="none" stroke="#000080" stroke-width=".2"/>
<path d="M169.9 53.3h3.8M169.9 52.4h3.8M171.8 50.5v1.9M171.8 53.3v1.9" fill="none" stroke="#00f" stroke-width=".25"/>
<path d="M171.8 57.6v2.4M169.4 60h4.8M170.1 60.7h3.4M170.8 61.5h1.9M171.5 62.2h.5" fill="none" stroke="#800000" stroke-width=".25"/>
<circle cx="181.3" cy="48.1" r=".48" fill="#000080"/>
<circle cx="181.3" cy="48.1" r=".48" fill="none" stroke="#000080" stroke-width=".2"/>
<path d="M181.4 48.1v2.4M181.4 55.2v2.4" fill="none" stroke="#000" stroke-width=".25"/>
<circle cx="181.3" cy="48.1" r=".48" fill="#000080"/>
<circle cx="181.3" cy="48.1" r=".48" fill="none" stroke="#000080" stroke-width=".2"/>
<path d="M179.5 53.3h3.7M179.5 52.4h3.7M181.4 50.5v1.9M181.4 53.3v1.9" fill="none" stroke="#00f" stroke-width=".25"/>
<path d="M181.4 57.6v2.4M179 60h4.7M179.7 60.7h3.3M180.4 61.5h1.9M181.1 62.2h.5" fill="none" stroke="#800000" stroke-width=".25"/>
<circle cx="190.9" cy="48.1" r=".48" fill="#000080"/>
<circle cx="190.9" cy="48.1" r=".48" fill="none" stroke="#000080" stroke-width=".2"/>
<path d="M190.9 48.1v2.4M190.9 55.2v2.4" fill="none" stroke="#000" stroke-width=".25"/>
<circle cx="190.9" cy="48.1" r=".48" fill="#000080"/>
<circle cx="190.9" cy="48.1" r=".48" fill="none" stroke="#000080" stroke-width=".2"/>
<path d="M189 53.3h3.8M189 52.4h3.8M190.9 50.5v1.9M190.9 53.3v1.9M151.7 62h1.9v5.6h-1.9zM156.4 62h2v5.6h-2zM161.2 62h1.9v5.6h-1.9z" fill="none" stroke="#00f" stroke-width=".25"/>
<path d="M190.9 57.6v2.4M188.5 60h4.8M189.2 60.7h3.4M190 61.5h1.9M190.7 62.2h.5" fill="none" stroke="#800000" stroke-width=".25"/>
<path d="M152.7 60v1.9M152.7 67.7v1.9M157.4 60v1.9M157.4 67.7v1.9M162.2 60v1.9M162.2 67.7v1.9" fill="none" stroke="#000" stroke-width=".25"/>
<path d="M188.5 69.6h45.4v83.6h-45.4z" fill-rule="evenodd" fill="#ffffb0"/>
<path d="M188.5 69.6h45.4v83.6h-45.4z" fill="none" stroke="#800000" stroke-width=".2"/>
<g fill="none" stroke="#000" stroke-width=".25">
<path d="M181.4 72h7.1M181.4 74.4h7.1M181.4 76.8h7.1M181.4 79.1h7.1M202.9 62.4v7.2M205.3 62.4v7.2M207.7 62.4v7.2M212.4 62.4v7.2M214.8 62.4v7.2M219.6 62.4v7.2M233.9 79.1h7.2M181.4 81.5h7.1"/>
<path d="M181.4 86.3h7.1M181.4 91.1h7.1M233.9 81.5h7.2M233.9 86.3h7.2M233.9 95.9h7.2M233.9 93.5h7.2M233.9 88.7h7.2M181.4 100.7h7.1M181.4 105.4h7.1M181.4 115h7.1M181.4 119.8h7.1M233.9 100.7h7.2"/>
<path d="M233.9 115h7.2M233.9 117.4h7.2M233.9 110.2h7.2M233.9 107.8h7.2M233.9 103h7.2M181.4 129.3h7.1M181.4 134.1h7.1M233.9 129.3h7.2M233.9 138.9h7.2M233.9 136.5h7.2M233.9 131.7h7.2M233.9 124.5h7.2"/>
<path d="M233.9 122.2h7.2M181.4 143.7h7.1M181.4 148.4h7.1M181.4 150.8h7.1M202.9 153.2v7.2M205.3 153.2v7.2M207.7 153.2v7.2M210 153.2v7.2M212.4 153.2v7.2M217.2 153.2v7.2M219.6 153.2v7.2M233.9 143.7h7.2"/>
<path d="M233.9 146.1h7.2"/>
</g>
<g fill="none" stroke="#800000" stroke-width=".25">
<path d="M145.5 27.8v2.3M145.5 28.9h2.4M145.5 46.9v2.4M145.5 48.1h2.4M151.5 52.9h2.4M152.7 52.9v2.3M200.5 167.6h4.8M201.2 168.3h3.3M201.9 169h1.9M202.6 169.7h.5M202.9 165.2v2.4M214.8 167.6h4.8"/>
<path d="M215.5 168.3h3.4M216.3 169h1.9M217 169.7h.5M217.2 165.2v2.4"/>
</g>
<circle cx="176.6" cy="91.1" r=".48" fill="#000080"/>
<circle cx="176.6" cy="91.1" r=".48" fill="none" stroke="#000080" stroke-width=".2"/>
<circle cx="176.6" cy="100.7" r=".48" fill="#000080"/>
<circle cx="176.6" cy="100.7" r=".48" fill="none" stroke="#000080" stroke-width=".2"/>
<path d="M176.6 91.1v1.9" fill="none" stroke="#000" stroke-width=".25"/>
<circle cx="176.6" cy="91.1" r=".48" fill="#000080"/>
<circle cx="176.6" cy="91.1" r=".48" fill="none" stroke="#000080" stroke-width=".2"/>
<path d="M176.6 98.8v1.9" fill="none" stroke="#000" stroke-width=".25"/>
<circle cx="176.6" cy="100.7" r=".48" fill="#000080"/>
<circle cx="176.6" cy="100.7" r=".48" fill="none" stroke="#000080" stroke-width=".2"/>
<path d="M175.6 93.1h2v5.6h-2z" fill="none" stroke="#00f" stroke-width=".25"/>
<circle cx="176.6" cy="105.4" r=".48" fill="#000080"/>
<circle cx="176.6" cy="105.4" r=".48" fill="none" stroke="#000080" stroke-width=".2"/>
<circle cx="176.6" cy="115" r=".48" fill="#000080"/>
<circle cx="176.6" cy="115" r=".48" fill="none" stroke="#000080" stroke-width=".2"/>
<path d="M176.6 105.4v1.9" fill="none" stroke="#000" stroke-width=".25"/>
<circle cx="176.6" cy="105.4" r=".48" fill="#000080"/>
<circle cx="176.6" cy="105.4" r=".48" fill="none" stroke="#000080" stroke-width=".2"/>
<path d="M176.6 113.1v1.9" fill="none" stroke="#000" stroke-width=".25"/>
<circle cx="176.6" cy="115" r=".48" fill="#000080"/>
<circle cx="176.6" cy="115" r=".48" fill="none" stroke="#000080" stroke-width=".2"/>
<path d="M175.6 107.4h2v5.6h-2z" fill="none" stroke="#00f" stroke-width=".25"/>
<circle cx="176.6" cy="119.8" r=".48" fill="#000080"/>
<circle cx="176.6" cy="119.8" r=".48" fill="none" stroke="#000080" stroke-width=".2"/>
<circle cx="176.6" cy="129.3" r=".48" fill="#000080"/>
<circle cx="176.6" cy="129.3" r=".48" fill="none" stroke="#000080" stroke-width=".2"/>
<path d="M176.6 119.8v1.9" fill="none" stroke="#000" stroke-width=".25"/>
<circle cx="176.6" cy="119.8" r=".48" fill="#000080"/>
<circle cx="176.6" cy="119.8" r=".48" fill="none" stroke="#000080" stroke-width=".2"/>
<path d="M176.6 127.4v1.9" fill="none" stroke="#000" stroke-width=".25"/>
<circle cx="176.6" cy="129.3" r=".48" fill="#000080"/>
<circle cx="176.6" cy="129.3" r=".48" fill="none" stroke="#000080" stroke-width=".2"/>
<path d="M175.6 121.7h2v5.7h-2z" fill="none" stroke="#00f" stroke-width=".25"/>
<circle cx="176.6" cy="134.1" r=".48" fill="#000080"/>
<circle cx="176.6" cy="134.1" r=".48" fill="none" stroke="#000080" stroke-width=".2"/>
<circle cx="176.6" cy="143.7" r=".48" fill="#000080"/>
<circle cx="176.6" cy="143.7" r=".48" fill="none" stroke="#000080" stroke-width=".2"/>
<path d="M176.6 134.1v1.9" fill="none" stroke="#000" stroke-width=".25"/>
<circle cx="176.6" cy="134.1" r=".48" fill="#000080"/>
<circle cx="176.6" cy="134.1" r=".48" fill="none" stroke="#000080" stroke-width=".2"/>
<path d="M176.6 141.8v1.9" fill="none" stroke="#000" stroke-width=".25"/>
<circle cx="176.6" cy="143.7" r=".48" fill="#000080"/>
<circle cx="176.6" cy="143.7" r=".48" fill="none" stroke="#000080" stroke-width=".2"/>
<path d="M175.6 136.1h2v5.6h-2z" fill="none" stroke="#00f" stroke-width=".25"/>
<path d="M248.3 77.9h10.7l1.2 1.2-1.2 1.2h-10.7z" fill-rule="evenodd" fill="#ffff80"/>
<path d="M248.3 77.9h10.7l1.2 1.2-1.2 1.2h-10.7z" fill="none" stroke="#800000" stroke-width=".2"/>
<path d="M248.3 80.3h10.7l1.2 1.2-1.2 1.2h-10.7z" fill-rule="evenodd" fill="#ffff80"/>
<path d="M248.3 80.3h10.7l1.2 1.2-1.2 1.2h-10.7z" fill="none" stroke="#800000" stroke-width=".2"/>
<path d="M248.3 85.1h10.7l1.2 1.2-1.2 1.2h-10.7z" fill-rule="evenodd" fill="#ffff80"/>
<path d="M248.3 85.1h10.7l1.2 1.2-1.2 1.2h-10.7z" fill="none" stroke="#800000" stroke-width=".2"/>
<path d="M248.3 87.5h10.7l1.2 1.2-1.2 1.2h-10.7z" fill-rule="evenodd" fill="#ffff80"/>
<path d="M248.3 87.5h10.7l1.2 1.2-1.2 1.2h-10.7z" fill="none" stroke="#800000" stroke-width=".2"/>
<path d="M248.3 92.3h10.7l1.2 1.2-1.2 1.2h-10.7z" fill-rule="evenodd" fill="#ffff80"/>
<path d="M248.3 92.3h10.7l1.2 1.2-1.2 1.2h-10.7z" fill="none" stroke="#800000" stroke-width=".2"/>
<path d="M248.3 94.7h10.7l1.2 1.2-1.2 1.2h-10.7z" fill-rule="evenodd" fill="#ffff80"/>
<path d="M248.3 94.7h10.7l1.2 1.2-1.2 1.2h-10.7z" fill="none" stroke="#800000" stroke-width=".2"/>
<path d="M248.3 99.5h10.7l1.2 1.2-1.2 1.1h-10.7z" fill-rule="evenodd" fill="#ffff80"/>
<path d="M248.3 99.5h10.7l1.2 1.2-1.2 1.1h-10.7z" fill="none" stroke="#800000" stroke-width=".2"/>
<path d="M248.3 101.8h10.7l1.2 1.2-1.2 1.2h-10.7z" fill-rule="evenodd" fill="#ffff80"/>
<path d="M248.3 101.8h10.7l1.2 1.2-1.2 1.2h-10.7z" fill="none" stroke="#800000" stroke-width=".2"/>
<path d="M248.3 106.6h10.7l1.2 1.2-1.2 1.2h-10.7z" fill-rule="evenodd" fill="#ffff80"/>
<path d="M248.3 106.6h10.7l1.2 1.2-1.2 1.2h-10.7z" fill="none" stroke="#800000" stroke-width=".2"/>
<path d="M248.3 109h10.7l1.2 1.2-1.2 1.2h-10.7z" fill-rule="evenodd" fill="#ffff80"/>
<path d="M248.3 109h10.7l1.2 1.2-1.2 1.2h-10.7z" fill="none" stroke="#800000" stroke-width=".2"/>
<path d="M248.3 113.8h10.7l1.2 1.2-1.2 1.2h-10.7z" fill-rule="evenodd" fill="#ffff80"/>
<path d="M248.3 113.8h10.7l1.2 1.2-1.2 1.2h-10.7z" fill="none" stroke="#800000" stroke-width=".2"/>
<path d="M248.3 116.2h10.7l1.2 1.2-1.2 1.2h-10.7z" fill-rule="evenodd" fill="#ffff80"/>
<path d="M248.3 116.2h10.7l1.2 1.2-1.2 1.2h-10.7z" fill="none" stroke="#800000" stroke-width=".2"/>
<path d="M248.3 121h10.7l1.2 1.2-1.2 1.2h-10.7z" fill-rule="evenodd" fill="#ffff80"/>
<path d="M248.3 121h10.7l1.2 1.2-1.2 1.2h-10.7z" fill="none" stroke="#800000" stroke-width=".2"/>
<path d="M248.3 123.4h10.7l1.2 1.1-1.2 1.2h-10.7z" fill-rule="evenodd" fill="#ffff80"/>
<path d="M248.3 123.4h10.7l1.2 1.1-1.2 1.2h-10.7z" fill="none" stroke="#800000" stroke-width=".2"/>
<path d="M248.3 128.1h10.7l1.2 1.2-1.2 1.2h-10.7z" fill-rule="evenodd" fill="#ffff80"/>
<path d="M248.3 128.1h10.7l1.2 1.2-1.2 1.2h-10.7z" fill="none" stroke="#800000" stroke-width=".2"/>
<path d="M248.3 130.5h10.7l1.2 1.2-1.2 1.2h-10.7z" fill-rule="evenodd" fill="#ffff80"/>
<path d="M248.3 130.5h10.7l1.2 1.2-1.2 1.2h-10.7z" fill="none" stroke="#800000" stroke-width=".2"/>
<path d="M248.3 135.3h10.7l1.2 1.2-1.2 1.2h-10.7z" fill-rule="evenodd" fill="#ffff80"/>
<path d="M248.3 135.3h10.7l1.2 1.2-1.2 1.2h-10.7z" fill="none" stroke="#800000" stroke-width=".2"/>
<path d="M248.3 137.7h10.7l1.2 1.2-1.2 1.2h-10.7z" fill-rule="evenodd" fill="#ffff80"/>
<path d="M248.3 137.7h10.7l1.2 1.2-1.2 1.2h-10.7z" fill="none" stroke="#800000" stroke-width=".2"/>
<path d="M248.3 142.5h10.7l1.2 1.2-1.2 1.2h-10.7z" fill-rule="evenodd" fill="#ffff80"/>
<path d="M248.3 142.5h10.7l1.2 1.2-1.2 1.2h-10.7z" fill="none" stroke="#800000" stroke-width=".2"/>
<path d="M248.3 144.9h10.7l1.2 1.2-1.2 1.2h-10.7z" fill-rule="evenodd" fill="#ffff80"/>
<path d="M248.3 144.9h10.7l1.2 1.2-1.2 1.2h-10.7z" fill="none" stroke="#800000" stroke-width=".2"/>
<path d="M112 70.8h15.6l1.2 1.2-1.2 1.2h-15.6z" fill-rule="evenodd" fill="#ffff80"/>
<path d="M112 70.8h15.6l1.2 1.2-1.2 1.2h-15.6z" fill="none" stroke="#800000" stroke-width=".2"/>
<path d="M112 73.2h15.6l1.2 1.2-1.2 1.2h-15.6z" fill-rule="evenodd" fill="#ffff80"/>
<path d="M112 73.2h15.6l1.2 1.2-1.2 1.2h-15.6z" fill="none" stroke="#800000" stroke-width=".2"/>
<path d="M112 75.6h15.6l1.2 1.1-1.2 1.2h-15.6z" fill-rule="evenodd" fill="#ffff80"/>
<path d="M112 75.6h15.6l1.2 1.1-1.2 1.2h-15.6z" fill="none" stroke="#800000" stroke-width=".2"/>
<path d="M155 86.3l1.2-1.2h10.8v2.4h-10.8z" fill-rule="evenodd" fill="#ffff80"/>
<path d="M155 86.3l1.2-1.2h10.8v2.4h-10.8z" fill="none" stroke="#800000" stroke-width=".2"/>
<path d="M112 77.9h15.6l1.2 1.2-1.2 1.2h-15.6z" fill-rule="evenodd" fill="#ffff80"/>
<path d="M112 77.9h15.6l1.2 1.2-1.2 1.2h-15.6z" fill="none" stroke="#800000" stroke-width=".2"/>
<path d="M112 80.3h15.6l1.2 1.2-1.2 1.2h-15.6z" fill-rule="evenodd" fill="#ffff80"/>
<path d="M112 80.3h15.6l1.2 1.2-1.2 1.2h-15.6z" fill="none" stroke="#800000" stroke-width=".2"/>
<path d="M28.3 115v2.4M90.5 115v2.4M28.3 122.2v2.3M90.5 122.2v2.3" fill="none" stroke="#000" stroke-width=".25"/>
<path d="M26.5 119.3h3.7M28.3 117.4v1.9M88.6 119.3h3.8M90.5 117.4v1.9M26.5 120.2h3.7M28.3 120.2v2M88.6 120.2h3.8M90.5 120.2v2" fill="none" stroke="#00f" stroke-width=".25"/>
<g fill="none" stroke="#800000" stroke-width=".25">
<path d="M12.8 107.8h2.4M14 107.8v2.4M25.9 129.3h4.8M26.7 130h3.3M27.4 130.8h1.9M28.1 131.5h.5M28.3 126.9v2.4M42.7 129.3h4.8M43.4 130h3.3M44.1 130.8h1.9M44.8 131.5h.5M45.1 126.9v2.4"/>
<path d="M88.1 129.3h4.8M88.8 130h3.4M89.5 130.8h2M90.3 131.5h.4M90.5 126.9v2.4"/>
</g>
<path d="M75.2 118.8l1.9 1.9M77.1 118.8l-1.9 1.9" fill="none" stroke="#f00" stroke-width=".2"/>
<path d="M54.6 110.2h14.4v12h-14.4z" fill-rule="evenodd" fill="#ffffb0"/>
<path d="M54.6 110.2h14.4v12h-14.4z" fill="none" stroke="#800000" stroke-width=".2"/>
<path d="M35.5 45.7v1.9M35.5 53.4v1.8M37.9 115v1.9M47.5 112.6h7.1M47.5 119.8h7.1M47.5 115h7.1M69 112.6h7.2M69 119.8h7.2M37.9 122.7v1.8" fill="none" stroke="#000" stroke-width=".25"/>
<path d="M34.5 47.6h1.9v5.7h-1.9zM36.9 116.9h1.9v5.7h-1.9z" fill="none" stroke="#00f" stroke-width=".25"/>
<path d="M35.5 57.6v2.4M33.1 60h4.8M33.8 60.7h3.4M34.6 61.5h1.9M35.3 62.2h.4M35.5 129.3h4.8M36.2 130h3.4M36.9 130.8h2M37.7 131.5h.4M37.9 126.9v2.4" fill="none" stroke="#800000" stroke-width=".25"/>
<path d="M21.2 89.9h10.7l1.2 1.2-1.2 1.2h-10.7z" fill-rule="evenodd" fill="#ffff80"/>
<path d="M21.2 89.9h10.7l1.2 1.2-1.2 1.2h-10.7z" fill="none" stroke="#800000" stroke-width=".2"/>
<path d="M16.4 33.7h1.9M24.1 33.7h1.8M116.8 33.7h4.2M122.2 33.7h4.2M116.8 43.3h4.2M122.2 43.3h4.2M16.4 112.6h1.9M24.1 112.6h1.8" fill="none" stroke="#000" stroke-width=".25"/>
<path d="M18.3 32.8h5.7v1.9h-5.7zM121.6 32.5h1.2l-1.2 2.4h-1.2zM121.6 42.1h1.2l-1.2 2.4h-1.2zM18.3 111.7h5.7v1.9h-5.7z" fill="none" stroke="#00f" stroke-width=".25"/>
<path d="M128.8 33.7h2.3M131.1 32.5v2.4M128.8 43.3h2.3M131.1 42.1v2.4" fill="none" stroke="#800000" stroke-width=".25"/>
<path d="M21.2 86.3l1.2-1.2h10.7v2.4h-10.7z" fill-rule="evenodd" fill="#ffff80"/>
<path d="M21.2 86.3l1.2-1.2h10.7v2.4h-10.7z" fill="none" stroke="#800000" stroke-width=".2"/>
<path d="M49.9 74.4v1.8M49.9 82v1.9M176.6 150.8v1.9M176.6 158.5v1.9" fill="none" stroke="#000" stroke-width=".25"/>
<path d="M48.9 76.3h1.9v5.7h-1.9zM175.6 152.8h2v5.6h-2z" fill="none" stroke="#00f" stroke-width=".25"/>
<path d="M48.7 72h2.3M49.9 72v2.4" fill="none" stroke="#800000" stroke-width=".25"/>
<path d="M83.3 146.1h16.8v21.5h-16.8z" fill-rule="evenodd" fill="#ffffb0"/>
<path d="M83.3 146.1h16.8v21.5h-16.8z" fill="none" stroke="#800000" stroke-width=".2"/>
<path d="M76.2 148.4h7.1M76.2 150.8h7.1M76.2 155.6h7.1M76.2 158h7.1M100.1 155.6h7.1M100.1 158h7.1M42.7 162.8v1.9M42.7 170.5v1.8M47.5 162.8v1.9M47.5 170.5v1.8M76.2 162.8h7.1M76.2 165.2h7.1" fill="none" stroke="#000" stroke-width=".25"/>
<path d="M43.9 155.6h2.4M45.1 155.6v2.4M71.4 170h4.8M72.1 170.7h3.3M72.8 171.4h1.9M73.5 172.1h.5M73.8 167.6v2.4" fill="none" stroke="#800000" stroke-width=".25"/>
<path d="M41.7 164.7h1.9v5.7h-1.9zM46.5 164.7h1.9v5.7h-1.9z" fill="none" stroke="#00f" stroke-width=".25"/>
<path d="M21.2 175.9h13.1l1.2 1.2-1.2 1.2h-13.1z" fill-rule="evenodd" fill="#ffff80"/>
<path d="M21.2 175.9h13.1l1.2 1.2-1.2 1.2h-13.1z" fill="none" stroke="#800000" stroke-width=".2"/>
<path d="M21.2 173.5h13.1l1.2 1.2-1.2 1.2h-13.1z" fill-rule="evenodd" fill="#ffff80"/>
<path d="M21.2 173.5h13.1l1.2 1.2-1.2 1.2h-13.1z" fill="none" stroke="#800000" stroke-width=".2"/>
<path d="M80.9 115v2.4M100.1 115v2.4M80.9 122.2v2.3M100.1 122.2v2.3M57 153.2v1.9M57 160.9v1.9" fill="none" stroke="#000" stroke-width=".25"/>
<path d="M79.1 119.3h3.7M80.9 117.4v1.9M98.2 119.3h3.7M100.1 117.4v1.9M79.1 120.2h3.7M80.9 120.2v2M98.2 120.2h3.7M100.1 120.2v2M56 155.2h1.9v5.6h-1.9z" fill="none" stroke="#00f" stroke-width=".25"/>
<g fill="none" stroke="#800000" stroke-width=".25">
<path d="M78.5 129.3h4.8M79.3 130h3.3M80 130.8h1.9M80.7 131.5h.5M80.9 126.9v2.4M97.7 129.3h4.8M98.4 130h3.3M99.1 130.8h1.9M99.8 131.5h.5M100.1 126.9v2.4M54.6 167.6h4.8M55.4 168.3h3.3"/>
<path d="M56.1 169h1.9M56.8 169.7h.5M57 165.2v2.4"/>
</g>
<path d="M21.2 149.6h13.1l1.2 1.2-1.2 1.2h-13.1z" fill-rule="evenodd" fill="#ffff80"/>
<path d="M21.2 149.6h13.1l1.2 1.2-1.2 1.2h-13.1z" fill="none" stroke="#800000" stroke-width=".2"/>
<path d="M109.6 160.4v1.9M109.6 168.1v1.9M114.4 160.4v1.9M114.4 168.1v1.9" fill="none" stroke="#000" stroke-width=".25"/>
<path d="M108.7 162.4h1.9v5.6h-1.9zM113.5 162.4h1.9v5.6h-1.9z" fill="none" stroke="#00f" stroke-width=".25"/>
<path d="M109.6 177.1h4.8M110.3 177.8h3.4M111.1 178.6h1.9M111.8 179.3h.5M112 174.7v2.4" fill="none" stroke="#800000" stroke-width=".25"/>
<path d="M113.4 154.1h1l.5-.5h.9l.5 .5h1M113.4 154.7h1l.5 .4h.9l.5-.4h1M113.4 156.5h1l.5-.5h.9l.5 .5h1M113.4 157.1h1l.5 .4h.9l.5-.4h1" fill="none" stroke="#d0a19e" stroke-width=".25"/>
<path d="M113.4 154.7l-1.4 .9M113.4 157.1l-1.4 .9" fill="none" stroke="#d0a19e" stroke-width=".2"/>
<path d="M113.2 153.8h1l.4-.5h1l.5 .5h.9M113.2 154.4h1l.4 .5h1l.5-.5h.9M113.2 156.2h1l.4-.5h1l.5 .5h.9M113.2 156.8h1l.4 .5h1l.5-.5h.9" fill="none" stroke="#f00" stroke-width=".25"/>
<path d="M113.2 154.4l-1.2 1.2M113.2 156.8l-1.2 1.2" fill="none" stroke="#f00" stroke-width=".2"/>
<circle cx="14" cy="33.7" r=".48" fill="#000080"/>
<circle cx="14" cy="33.7" r=".48" fill="none" stroke="#000080" stroke-width=".2"/>
<path d="M14 33.7v2.4" fill="none" stroke="#000" stroke-width=".25"/>
<circle cx="14" cy="33.7" r=".48" fill="#000080"/>
<circle cx="14" cy="33.7" r=".48" fill="none" stroke="#000080" stroke-width=".2"/>
<circle cx="14" cy="37.3" r="1.19" fill="none" stroke="#000" stroke-width=".25"/>
<circle cx="30.7" cy="33.7" r=".48" fill="#000080"/>
<circle cx="30.7" cy="33.7" r=".48" fill="none" stroke="#000080" stroke-width=".2"/>
<path d="M30.7 31.3v2.4" fill="none" stroke="#000" stroke-width=".25"/>
<circle cx="30.7" cy="33.7" r=".48" fill="#000080"/>
<circle cx="30.7" cy="33.7" r=".48" fill="none" stroke="#000080" stroke-width=".2"/>
<circle cx="30.7" cy="30.1" r="1.2" fill="none" stroke="#000" stroke-width=".25"/>
<circle cx="14" cy="112.6" r=".48" fill="#000080"/>
<circle cx="14" cy="112.6" r=".48" fill="none" stroke="#000080" stroke-width=".2"/>
<path d="M14 112.6v2.4" fill="none" stroke="#000" stroke-width=".25"/>
<circle cx="14" cy="112.6" r=".48" fill="#000080"/>
<circle cx="14" cy="112.6" r=".48" fill="none" stroke="#000080" stroke-width=".2"/>
<circle cx="14" cy="116.2" r="1.2" fill="none" stroke="#000" stroke-width=".25"/>
<circle cx="30.7" cy="112.6" r=".48" fill="#000080"/>
<circle cx="30.7" cy="112.6" r=".48" fill="none" stroke="#000080" stroke-width=".2"/>
<path d="M30.7 110.2v2.4" fill="none" stroke="#000" stroke-width=".25"/>
<circle cx="30.7" cy="112.6" r=".48" fill="#000080"/>
<circle cx="30.7" cy="112.6" r=".48" fill="none" stroke="#000080" stroke-width=".2"/>
<circle cx="30.7" cy="109" r="1.19" fill="none" stroke="#000" stroke-width=".25"/>
<circle cx="35.5" cy="86.3" r=".48" fill="#000080"/>
<circle cx="35.5" cy="86.3" r=".48" fill="none" stroke="#000080" stroke-width=".2"/>
<path d="M35.5 83.9v2.4" fill="none" stroke="#000" stroke-width=".25"/>
<circle cx="35.5" cy="86.3" r=".48" fill="#000080"/>
<circle cx="35.5" cy="86.3" r=".48" fill="none" stroke="#000080" stroke-width=".2"/>
<circle cx="35.5" cy="82.7" r="1.2" fill="none" stroke="#000" stroke-width=".25"/>
<circle cx="35.5" cy="91.1" r=".48" fill="#000080"/>
<circle cx="35.5" cy="91.1" r=".48" fill="none" stroke="#000080" stroke-width=".2"/>
<path d="M35.5 91.1v2.4" fill="none" stroke="#000" stroke-width=".25"/>
<circle cx="35.5" cy="91.1" r=".48" fill="#000080"/>
<circle cx="35.5" cy="91.1" r=".48" fill="none" stroke="#000080" stroke-width=".2"/>
<circle cx="35.5" cy="94.7" r="1.2" fill="none" stroke="#000" stroke-width=".25"/>
<circle cx="37.9" cy="150.8" r=".48" fill="#000080"/>
<circle cx="37.9" cy="150.8" r=".48" fill="none" stroke="#000080" stroke-width=".2"/>
<path d="M37.9 148.4v2.4" fill="none" stroke="#000" stroke-width=".25"/>
<circle cx="37.9" cy="150.8" r=".48" fill="#000080"/>
<circle cx="37.9" cy="150.8" r=".48" fill="none" stroke="#000080" stroke-width=".2"/>
<circle cx="37.9" cy="147.2" r="1.2" fill="none" stroke="#000" stroke-width=".25"/>
<circle cx="37.9" cy="174.7" r=".48" fill="#000080"/>
<circle cx="37.9" cy="174.7" r=".48" fill="none" stroke="#000080" stroke-width=".2"/>
<path d="M37.9 172.3v2.4" fill="none" stroke="#000" stroke-width=".25"/>
<circle cx="37.9" cy="174.7" r=".48" fill="#000080"/>
<circle cx="37.9" cy="174.7" r=".48" fill="none" stroke="#000080" stroke-width=".2"/>
<circle cx="37.9" cy="171.2" r="1.19" fill="none" stroke="#000" stroke-width=".25"/>
<circle cx="37.9" cy="177.1" r=".48" fill="#000080"/>
<circle cx="37.9" cy="177.1" r=".48" fill="none" stroke="#000080" stroke-width=".2"/>
<path d="M37.9 177.1v2.4" fill="none" stroke="#000" stroke-width=".25"/>
<circle cx="37.9" cy="177.1" r=".48" fill="#000080"/>
<circle cx="37.9" cy="177.1" r=".48" fill="none" stroke="#000080" stroke-width=".2"/>
<g fill="none" stroke="#000" stroke-width=".25">
<path d="M128.8 138.9h4.7M128.8 141.3v2.4M140.7 158h1.9M148.4 158h1.9M150.3 155.6h1.9M157.9 155.6h1.9"/>
<circle cx="37.9" cy="180.7" r="1.19"/>
<circle cx="37.9" cy="180.7" r="1.2"/>
</g>
<path d="M103.6 107.8h2.4M104.8 107.8v2.4M70.2 143.7h2.4M71.4 143.7v2.4" fill="none" stroke="#800000" stroke-width=".25"/>
<g fill="none" stroke="#00f" stroke-width=".25">
<path d="M142.7 157.1h5.6v1.9h-5.6zM152.2 154.7h5.7v1.9h-5.7z"/>
<circle cx="128.7" cy="138.9" r="2.39"/>
<circle cx="128.8" cy="138.9" r="2.39"/>
</g>
<circle cx="128.8" cy="138.9" r=".6" fill="#00f"/>
<circle cx="128.8" cy="138.9" r=".6" fill="none" stroke="#00f" stroke-width=".2"/>
<path d="M126.4 146.1h4.7M127.1 146.8h3.3M127.8 147.5h1.9M128.5 148.2h.5M128.8 143.7v2.4" fill="none" stroke="#800000" stroke-width=".25"/>
<circle cx="145.5" cy="138.9" r="2.39" fill="none" stroke="#00f" stroke-width=".25"/>
<path d="M140.7 138.9h4.8M145.5 141.3v2.4" fill="none" stroke="#000" stroke-width=".25"/>
<circle cx="145.5" cy="138.9" r=".6" fill="#00f"/>
<circle cx="145.5" cy="138.9" r=".6" fill="none" stroke="#00f" stroke-width=".2"/>
<path d="M143.1 146.1h4.8M143.8 146.8h3.4M144.5 147.5h1.9M145.2 148.2h.5M145.5 143.7v2.4" fill="none" stroke="#800000" stroke-width=".25"/>
<path d="M45.1 48.1h-2.4v2.4h2.4" fill="none" stroke="#000080" stroke-width=".25"/>
<circle cx="42.7" cy="50.5" r=".48" fill="#000080"/>
<circle cx="42.7" cy="50.5" r=".48" fill="none" stroke="#000080" stroke-width=".2"/>
<path d="M42.7 50.5v7.1" fill="none" stroke="#000080" stroke-width=".25"/>
<circle cx="42.7" cy="50.5" r=".48" fill="#000080"/>
<circle cx="42.7" cy="50.5" r=".48" fill="none" stroke="#000080" stroke-width=".2"/>
<path d="M42.7 33.7v2.4h2.4" fill="none" stroke="#000080" stroke-width=".25"/>
<circle cx="42.7" cy="36.1" r=".48" fill="#000080"/>
<circle cx="42.7" cy="36.1" r=".48" fill="none" stroke="#000080" stroke-width=".2"/>
<circle cx="42.7" cy="33.7" r=".48" fill="#000080"/>
<circle cx="42.7" cy="33.7" r=".48" fill="none" stroke="#000080" stroke-width=".2"/>
<path d="M42.7 36.1v4.8h2.4" fill="none" stroke="#000080" stroke-width=".25"/>
<circle cx="42.7" cy="36.1" r=".48" fill="#000080"/>
<circle cx="42.7" cy="36.1" r=".48" fill="none" stroke="#000080" stroke-width=".2"/>
<path d="M28.3 45.7v2.4M78.5 50.5h2.4v2.4M92.9 45.7v2.4M80.9 62.4v2.4" fill="none" stroke="#000080" stroke-width=".25"/>
<circle cx="92.9" cy="48.1" r=".48" fill="#000080"/>
<circle cx="92.9" cy="48.1" r=".48" fill="none" stroke="#000080" stroke-width=".2"/>
<path d="M92.9 33.7v2.4M107.2 45.7v2.4M100.1 62.4v2.4" fill="none" stroke="#000080" stroke-width=".25"/>
<circle cx="92.9" cy="33.7" r=".48" fill="#000080"/>
<circle cx="92.9" cy="33.7" r=".48" fill="none" stroke="#000080" stroke-width=".2"/>
<path d="M100.1 45.7v2.4" fill="none" stroke="#000080" stroke-width=".25"/>
<circle cx="100.1" cy="48.1" r=".48" fill="#000080"/>
<circle cx="100.1" cy="48.1" r=".48" fill="none" stroke="#000080" stroke-width=".2"/>
<path d="M100.1 33.7v2.4" fill="none" stroke="#000080" stroke-width=".25"/>
<circle cx="100.1" cy="33.7" r=".48" fill="#000080"/>
<circle cx="100.1" cy="33.7" r=".48" fill="none" stroke="#000080" stroke-width=".2"/>
<path d="M162.2 69.6v2.4h19.2" fill="none" stroke="#000080" stroke-width=".25"/>
<circle cx="162.2" cy="72" r=".48" fill="#000080"/>
<circle cx="162.2" cy="72" r=".48" fill="none" stroke="#000080" stroke-width=".2"/>
<path d="M157.4 69.6v4.8h24" fill="none" stroke="#000080" stroke-width=".25"/>
<circle cx="157.4" cy="74.4" r=".48" fill="#000080"/>
<circle cx="157.4" cy="74.4" r=".48" fill="none" stroke="#000080" stroke-width=".2"/>
<path d="M152.7 69.6v7.2h28.7" fill="none" stroke="#000080" stroke-width=".25"/>
<circle cx="152.7" cy="76.7" r=".48" fill="#000080"/>
<circle cx="152.7" cy="76.7" r=".48" fill="none" stroke="#000080" stroke-width=".2"/>
<path d="M128.8 72h33.4" fill="none" stroke="#000080" stroke-width=".25"/>
<circle cx="162.2" cy="72" r=".48" fill="#000080"/>
<circle cx="162.2" cy="72" r=".48" fill="none" stroke="#000080" stroke-width=".2"/>
<circle cx="145.5" cy="72" r=".48" fill="#000080"/>
<circle cx="145.5" cy="72" r=".48" fill="none" stroke="#000080" stroke-width=".2"/>
<path d="M128.8 74.4h28.6" fill="none" stroke="#000080" stroke-width=".25"/>
<circle cx="157.4" cy="74.4" r=".48" fill="#000080"/>
<circle cx="157.4" cy="74.4" r=".48" fill="none" stroke="#000080" stroke-width=".2"/>
<circle cx="140.7" cy="74.4" r=".48" fill="#000080"/>
<circle cx="140.7" cy="74.4" r=".48" fill="none" stroke="#000080" stroke-width=".2"/>
<path d="M128.8 76.7h23.9" fill="none" stroke="#000080" stroke-width=".25"/>
<circle cx="135.9" cy="76.7" r=".48" fill="#000080"/>
<circle cx="135.9" cy="76.7" r=".48" fill="none" stroke="#000080" stroke-width=".2"/>
<circle cx="152.7" cy="76.7" r=".48" fill="#000080"/>
<circle cx="152.7" cy="76.7" r=".48" fill="none" stroke="#000080" stroke-width=".2"/>
<path d="M207.7 162.8h-4.8v2.4" fill="none" stroke="#000080" stroke-width=".25"/>
<circle cx="202.9" cy="162.8" r=".48" fill="#000080"/>
<circle cx="202.9" cy="162.8" r=".48" fill="none" stroke="#000080" stroke-width=".2"/>
<circle cx="205.3" cy="162.8" r=".48" fill="#000080"/>
<circle cx="205.3" cy="162.8" r=".48" fill="none" stroke="#000080" stroke-width=".2"/>
<circle cx="207.7" cy="162.8" r=".48" fill="#000080"/>
<circle cx="207.7" cy="162.8" r=".48" fill="none" stroke="#000080" stroke-width=".2"/>
<path d="M205.3 160.4v2.4" fill="none" stroke="#000080" stroke-width=".25"/>
<circle cx="205.3" cy="162.8" r=".48" fill="#000080"/>
<circle cx="205.3" cy="162.8" r=".48" fill="none" stroke="#000080" stroke-width=".2"/>
<path d="M207.7 160.4v2.4" fill="none" stroke="#000080" stroke-width=".25"/>
<circle cx="207.7" cy="162.8" r=".48" fill="#000080"/>
<circle cx="207.7" cy="162.8" r=".48" fill="none" stroke="#000080" stroke-width=".2"/>
<path d="M210 160.4v2.4" fill="none" stroke="#000080" stroke-width=".25"/>
<circle cx="210" cy="162.8" r=".48" fill="#000080"/>
<circle cx="210" cy="162.8" r=".48" fill="none" stroke="#000080" stroke-width=".2"/>
<path d="M217.2 160.4v2.4h2.4v-2.4" fill="none" stroke="#000080" stroke-width=".25"/>
<circle cx="217.2" cy="162.8" r=".48" fill="#000080"/>
<circle cx="217.2" cy="162.8" r=".48" fill="none" stroke="#000080" stroke-width=".2"/>
<path d="M217.2 162.8v2.4" fill="none" stroke="#000080" stroke-width=".25"/>
<circle cx="217.2" cy="162.8" r=".48" fill="#000080"/>
<circle cx="217.2" cy="162.8" r=".48" fill="none" stroke="#000080" stroke-width=".2"/>
<path d="M212.4 160.4v2.4h-4.7" fill="none" stroke="#000080" stroke-width=".25"/>
<circle cx="210" cy="162.8" r=".48" fill="#000080"/>
<circle cx="210" cy="162.8" r=".48" fill="none" stroke="#000080" stroke-width=".2"/>
<circle cx="207.7" cy="162.8" r=".48" fill="#000080"/>
<circle cx="207.7" cy="162.8" r=".48" fill="none" stroke="#000080" stroke-width=".2"/>
<path d="M202.9 160.4v2.4" fill="none" stroke="#000080" stroke-width=".25"/>
<circle cx="202.9" cy="162.8" r=".48" fill="#000080"/>
<circle cx="202.9" cy="162.8" r=".48" fill="none" stroke="#000080" stroke-width=".2"/>
<path d="M181.4 48.1h26.3v11.9" fill="none" stroke="#000080" stroke-width=".25"/>
<circle cx="207.7" cy="60" r=".48" fill="#000080"/>
<circle cx="207.7" cy="60" r=".48" fill="none" stroke="#000080" stroke-width=".2"/>
<circle cx="207.7" cy="48.1" r=".48" fill="#000080"/>
<circle cx="207.7" cy="48.1" r=".48" fill="none" stroke="#000080" stroke-width=".2"/>
<circle cx="190.9" cy="48.1" r=".48" fill="#000080"/>
<circle cx="190.9" cy="48.1" r=".48" fill="none" stroke="#000080" stroke-width=".2"/>
<circle cx="181.3" cy="48.1" r=".48" fill="#000080"/>
<circle cx="181.3" cy="48.1" r=".48" fill="none" stroke="#000080" stroke-width=".2"/>
<path d="M255.5 28.9h-43.1v31.1" fill="none" stroke="#000080" stroke-width=".25"/>
<circle cx="212.4" cy="60" r=".48" fill="#000080"/>
<circle cx="212.4" cy="60" r=".48" fill="none" stroke="#000080" stroke-width=".2"/>
<circle cx="217.2" cy="29" r=".48" fill="#000080"/>
<circle cx="217.2" cy="29" r=".48" fill="none" stroke="#000080" stroke-width=".2"/>
<circle cx="226.8" cy="29" r=".48" fill="#000080"/>
<circle cx="226.8" cy="29" r=".48" fill="none" stroke="#000080" stroke-width=".2"/>
<circle cx="236.3" cy="29" r=".48" fill="#000080"/>
<circle cx="236.3" cy="29" r=".48" fill="none" stroke="#000080" stroke-width=".2"/>
<circle cx="245.9" cy="29" r=".48" fill="#000080"/>
<circle cx="245.9" cy="29" r=".48" fill="none" stroke="#000080" stroke-width=".2"/>
<path d="M152.7 60v-2.4h9.5v2.4" fill="none" stroke="#000080" stroke-width=".25"/>
<circle cx="152.7" cy="57.6" r=".48" fill="#000080"/>
<circle cx="152.7" cy="57.6" r=".48" fill="none" stroke="#000080" stroke-width=".2"/>
<circle cx="157.4" cy="57.6" r=".48" fill="#000080"/>
<circle cx="157.4" cy="57.6" r=".48" fill="none" stroke="#000080" stroke-width=".2"/>
<path d="M157.4 57.6v2.4" fill="none" stroke="#000080" stroke-width=".25"/>
<circle cx="157.4" cy="57.6" r=".48" fill="#000080"/>
<circle cx="157.4" cy="57.6" r=".48" fill="none" stroke="#000080" stroke-width=".2"/>
<path d="M152.7 55.2v2.4" fill="none" stroke="#000080" stroke-width=".25"/>
<circle cx="152.7" cy="57.6" r=".48" fill="#000080"/>
<circle cx="152.7" cy="57.6" r=".48" fill="none" stroke="#000080" stroke-width=".2"/>
<path d="M255.5 48.1h-35.9v14.3" fill="none" stroke="#000080" stroke-width=".25"/>
<circle cx="236.3" cy="48.1" r=".48" fill="#000080"/>
<circle cx="236.3" cy="48.1" r=".48" fill="none" stroke="#000080" stroke-width=".2"/>
<circle cx="226.8" cy="48.1" r=".48" fill="#000080"/>
<circle cx="226.8" cy="48.1" r=".48" fill="none" stroke="#000080" stroke-width=".2"/>
<path d="M205.3 60v2.4" fill="none" stroke="#000080" stroke-width=".25"/>
<circle cx="205.3" cy="60" r=".48" fill="#000080"/>
<circle cx="205.3" cy="60" r=".48" fill="none" stroke="#000080" stroke-width=".2"/>
<path d="M212.4 62.4v-2.4h2.4v2.4" fill="none" stroke="#000080" stroke-width=".25"/>
<circle cx="212.4" cy="60" r=".48" fill="#000080"/>
<circle cx="212.4" cy="60" r=".48" fill="none" stroke="#000080" stroke-width=".2"/>
<path d="M202.9 62.4v-2.4h4.8v2.4" fill="none" stroke="#000080" stroke-width=".25"/>
<circle cx="205.3" cy="60" r=".48" fill="#000080"/>
<circle cx="205.3" cy="60" r=".48" fill="none" stroke="#000080" stroke-width=".2"/>
<circle cx="207.7" cy="60" r=".48" fill="#000080"/>
<circle cx="207.7" cy="60" r=".48" fill="none" stroke="#000080" stroke-width=".2"/>
<path d="M147.9 28.9h59.8v19.2" fill="none" stroke="#000080" stroke-width=".25"/>
<circle cx="207.7" cy="48.1" r=".48" fill="#000080"/>
<circle cx="207.7" cy="48.1" r=".48" fill="none" stroke="#000080" stroke-width=".2"/>
<circle cx="200.5" cy="29" r=".48" fill="#000080"/>
<circle cx="200.5" cy="29" r=".48" fill="none" stroke="#000080" stroke-width=".2"/>
<circle cx="190.9" cy="29" r=".48" fill="#000080"/>
<circle cx="190.9" cy="29" r=".48" fill="none" stroke="#000080" stroke-width=".2"/>
<circle cx="181.3" cy="29" r=".48" fill="#000080"/>
<circle cx="181.3" cy="29" r=".48" fill="none" stroke="#000080" stroke-width=".2"/>
<circle cx="171.8" cy="28.9" r=".48" fill="#000080"/>
<circle cx="171.8" cy="28.9" r=".48" fill="none" stroke="#000080" stroke-width=".2"/>
<circle cx="162.2" cy="28.9" r=".48" fill="#000080"/>
<circle cx="162.2" cy="28.9" r=".48" fill="none" stroke="#000080" stroke-width=".2"/>
<circle cx="152.7" cy="28.9" r=".48" fill="#000080"/>
<circle cx="152.7" cy="28.9" r=".48" fill="none" stroke="#000080" stroke-width=".2"/>
<path d="M147.9 48.1h33.5" fill="none" stroke="#000080" stroke-width=".25"/>
<circle cx="171.8" cy="48.1" r=".48" fill="#000080"/>
<circle cx="171.8" cy="48.1" r=".48" fill="none" stroke="#000080" stroke-width=".2"/>
<circle cx="181.3" cy="48.1" r=".48" fill="#000080"/>
<circle cx="181.3" cy="48.1" r=".48" fill="none" stroke="#000080" stroke-width=".2"/>
<path d="M167 91.1h14.4" fill="none" stroke="#000080" stroke-width=".25"/>
<circle cx="176.6" cy="91.1" r=".48" fill="#000080"/>
<circle cx="176.6" cy="91.1" r=".48" fill="none" stroke="#000080" stroke-width=".2"/>
<path d="M167 100.7h14.4" fill="none" stroke="#000080" stroke-width=".25"/>
<circle cx="176.6" cy="100.7" r=".48" fill="#000080"/>
<circle cx="176.6" cy="100.7" r=".48" fill="none" stroke="#000080" stroke-width=".2"/>
<path d="M167 105.4h14.4" fill="none" stroke="#000080" stroke-width=".25"/>
<circle cx="176.6" cy="105.4" r=".48" fill="#000080"/>
<circle cx="176.6" cy="105.4" r=".48" fill="none" stroke="#000080" stroke-width=".2"/>
<path d="M167 115h14.4" fill="none" stroke="#000080" stroke-width=".25"/>
<circle cx="176.6" cy="115" r=".48" fill="#000080"/>
<circle cx="176.6" cy="115" r=".48" fill="none" stroke="#000080" stroke-width=".2"/>
<path d="M167 119.8h14.4" fill="none" stroke="#000080" stroke-width=".25"/>
<circle cx="176.6" cy="119.8" r=".48" fill="#000080"/>
<circle cx="176.6" cy="119.8" r=".48" fill="none" stroke="#000080" stroke-width=".2"/>
<path d="M167 129.3h14.4" fill="none" stroke="#000080" stroke-width=".25"/>
<circle cx="176.6" cy="129.3" r=".48" fill="#000080"/>
<circle cx="176.6" cy="129.3" r=".48" fill="none" stroke="#000080" stroke-width=".2"/>
<path d="M167 134.1h14.4" fill="none" stroke="#000080" stroke-width=".25"/>
<circle cx="176.6" cy="134.1" r=".48" fill="#000080"/>
<circle cx="176.6" cy="134.1" r=".48" fill="none" stroke="#000080" stroke-width=".2"/>
<path d="M167 143.7h14.4" fill="none" stroke="#000080" stroke-width=".25"/>
<circle cx="176.6" cy="143.7" r=".48" fill="#000080"/>
<circle cx="176.6" cy="143.7" r=".48" fill="none" stroke="#000080" stroke-width=".2"/>
<g fill="none" stroke="#000080" stroke-width=".25">
<path d="M128.8 79.1h52.6M241.1 79.1h7.2M241.1 81.5h7.2M241.1 86.3h7.2M241.1 88.7h7.2M241.1 93.5h7.2M241.1 95.9h7.2M241.1 100.7h7.2M241.1 103h7.2M241.1 107.8h7.2M241.1 110.2h7.2M241.1 115h7.2"/>
<path d="M241.1 117.4h7.2M241.1 122.2h7.2M241.1 124.5h7.2M241.1 129.3h7.2M241.1 131.7h7.2M241.1 136.5h7.2M241.1 138.9h7.2M241.1 143.7h7.2M241.1 146.1h7.2"/>
</g>
<circle cx="140.7" cy="79.1" r=".48" fill="#000080"/>
<circle cx="140.7" cy="79.1" r=".48" fill="none" stroke="#000080" stroke-width=".2"/>
<path d="M128.8 81.5h52.6" fill="none" stroke="#000080" stroke-width=".25"/>
<circle cx="135.9" cy="81.5" r=".48" fill="#000080"/>
<circle cx="135.9" cy="81.5" r=".48" fill="none" stroke="#000080" stroke-width=".2"/>
<path d="M35.5 55.2v2.4M45.1 43.3h-9.6v2.4M167 86.3h14.4M47.5 119.8h-2.4v7.1M47.5 112.6h-19.2v2.4" fill="none" stroke="#000080" stroke-width=".25"/>
<circle cx="30.7" cy="112.6" r=".48" fill="#000080"/>
<circle cx="30.7" cy="112.6" r=".48" fill="none" stroke="#000080" stroke-width=".2"/>
<circle cx="28.3" cy="112.6" r=".48" fill="#000080"/>
<circle cx="28.3" cy="112.6" r=".48" fill="none" stroke="#000080" stroke-width=".2"/>
<path d="M33.1 91.1h14.4M37.9 115h9.6M28.3 124.5v2.4M37.9 124.5v2.4" fill="none" stroke="#000080" stroke-width=".25"/>
<circle cx="35.5" cy="91.1" r=".48" fill="#000080"/>
<circle cx="35.5" cy="91.1" r=".48" fill="none" stroke="#000080" stroke-width=".2"/>
<path d="M28.3 33.7h16.8" fill="none" stroke="#000080" stroke-width=".25"/>
<circle cx="28.3" cy="33.7" r=".48" fill="#000080"/>
<circle cx="28.3" cy="33.7" r=".48" fill="none" stroke="#000080" stroke-width=".2"/>
<circle cx="30.7" cy="33.7" r=".48" fill="#000080"/>
<circle cx="30.7" cy="33.7" r=".48" fill="none" stroke="#000080" stroke-width=".2"/>
<circle cx="42.7" cy="33.7" r=".48" fill="#000080"/>
<circle cx="42.7" cy="33.7" r=".48" fill="none" stroke="#000080" stroke-width=".2"/>
<path d="M14 31.3v2.4h2.4" fill="none" stroke="#000080" stroke-width=".25"/>
<circle cx="14" cy="33.7" r=".48" fill="#000080"/>
<circle cx="14" cy="33.7" r=".48" fill="none" stroke="#000080" stroke-width=".2"/>
<path d="M25.9 33.7h2.4" fill="none" stroke="#000080" stroke-width=".25"/>
<circle cx="28.3" cy="33.7" r=".48" fill="#000080"/>
<circle cx="28.3" cy="33.7" r=".48" fill="none" stroke="#000080" stroke-width=".2"/>
<path d="M28.3 33.7v2.4" fill="none" stroke="#000080" stroke-width=".25"/>
<circle cx="28.3" cy="33.7" r=".48" fill="#000080"/>
<circle cx="28.3" cy="33.7" r=".48" fill="none" stroke="#000080" stroke-width=".2"/>
<path d="M14 110.2v2.4h2.4" fill="none" stroke="#000080" stroke-width=".25"/>
<circle cx="14" cy="112.6" r=".48" fill="#000080"/>
<circle cx="14" cy="112.6" r=".48" fill="none" stroke="#000080" stroke-width=".2"/>
<path d="M25.9 112.6h2.4" fill="none" stroke="#000080" stroke-width=".25"/>
<circle cx="28.3" cy="112.6" r=".48" fill="#000080"/>
<circle cx="28.3" cy="112.6" r=".48" fill="none" stroke="#000080" stroke-width=".2"/>
<path d="M114.4 33.7v9.6h2.4" fill="none" stroke="#000080" stroke-width=".25"/>
<circle cx="114.4" cy="33.7" r=".48" fill="#000080"/>
<circle cx="114.4" cy="33.7" r=".48" fill="none" stroke="#000080" stroke-width=".2"/>
<path d="M100.1 33.7h16.7M126.4 33.7h2.4M126.4 43.3h2.4" fill="none" stroke="#000080" stroke-width=".25"/>
<circle cx="100.1" cy="33.7" r=".48" fill="#000080"/>
<circle cx="100.1" cy="33.7" r=".48" fill="none" stroke="#000080" stroke-width=".2"/>
<circle cx="107.2" cy="33.7" r=".48" fill="#000080"/>
<circle cx="107.2" cy="33.7" r=".48" fill="none" stroke="#000080" stroke-width=".2"/>
<circle cx="112" cy="33.7" r=".48" fill="#000080"/>
<circle cx="112" cy="33.7" r=".48" fill="none" stroke="#000080" stroke-width=".2"/>
<circle cx="114.4" cy="33.7" r=".48" fill="#000080"/>
<circle cx="114.4" cy="33.7" r=".48" fill="none" stroke="#000080" stroke-width=".2"/>
<path d="M78.5 40.9h9.6v7.2h12v4.8" fill="none" stroke="#000080" stroke-width=".25"/>
<circle cx="100.1" cy="48.1" r=".48" fill="#000080"/>
<circle cx="100.1" cy="48.1" r=".48" fill="none" stroke="#000080" stroke-width=".2"/>
<circle cx="92.9" cy="48.1" r=".48" fill="#000080"/>
<circle cx="92.9" cy="48.1" r=".48" fill="none" stroke="#000080" stroke-width=".2"/>
<path d="M78.5 33.7h9.6v2.4h-9.6" fill="none" stroke="#000080" stroke-width=".25"/>
<circle cx="88.1" cy="33.7" r=".48" fill="#000080"/>
<circle cx="88.1" cy="33.7" r=".48" fill="none" stroke="#000080" stroke-width=".2"/>
<path d="M88.1 33.7h12" fill="none" stroke="#000080" stroke-width=".25"/>
<circle cx="88.1" cy="33.7" r=".48" fill="#000080"/>
<circle cx="88.1" cy="33.7" r=".48" fill="none" stroke="#000080" stroke-width=".2"/>
<circle cx="92.9" cy="33.7" r=".48" fill="#000080"/>
<circle cx="92.9" cy="33.7" r=".48" fill="none" stroke="#000080" stroke-width=".2"/>
<circle cx="100.1" cy="33.7" r=".48" fill="#000080"/>
<circle cx="100.1" cy="33.7" r=".48" fill="none" stroke="#000080" stroke-width=".2"/>
<path d="M107.2 33.7v2.4" fill="none" stroke="#000080" stroke-width=".25"/>
<circle cx="107.2" cy="33.7" r=".48" fill="#000080"/>
<circle cx="107.2" cy="33.7" r=".48" fill="none" stroke="#000080" stroke-width=".2"/>
<path d="M78.5 45.7h7.2M49.9 83.9v2.4h-16.8" fill="none" stroke="#000080" stroke-width=".25"/>
<circle cx="35.5" cy="86.3" r=".48" fill="#000080"/>
<circle cx="35.5" cy="86.3" r=".48" fill="none" stroke="#000080" stroke-width=".2"/>
<path d="M76.2 162.8h-2.4v4.8" fill="none" stroke="#000080" stroke-width=".25"/>
<circle cx="73.8" cy="165.2" r=".48" fill="#000080"/>
<circle cx="73.8" cy="165.2" r=".48" fill="none" stroke="#000080" stroke-width=".2"/>
<path d="M73.8 165.2h2.4" fill="none" stroke="#000080" stroke-width=".25"/>
<circle cx="73.8" cy="165.2" r=".48" fill="#000080"/>
<circle cx="73.8" cy="165.2" r=".48" fill="none" stroke="#000080" stroke-width=".2"/>
<path d="M45.1 160.4h-2.4v2.4" fill="none" stroke="#000080" stroke-width=".25"/>
<circle cx="45.1" cy="160.4" r=".48" fill="#000080"/>
<circle cx="45.1" cy="160.4" r=".48" fill="none" stroke="#000080" stroke-width=".2"/>
<path d="M45.1 158v2.4h2.4v2.4" fill="none" stroke="#000080" stroke-width=".25"/>
<circle cx="45.1" cy="160.4" r=".48" fill="#000080"/>
<circle cx="45.1" cy="160.4" r=".48" fill="none" stroke="#000080" stroke-width=".2"/>
<path d="M42.7 172.3v2.4" fill="none" stroke="#000080" stroke-width=".25"/>
<circle cx="42.7" cy="174.7" r=".48" fill="#000080"/>
<circle cx="42.7" cy="174.7" r=".48" fill="none" stroke="#000080" stroke-width=".2"/>
<path d="M47.5 172.3v4.8" fill="none" stroke="#000080" stroke-width=".25"/>
<circle cx="47.5" cy="177.1" r=".48" fill="#000080"/>
<circle cx="47.5" cy="177.1" r=".48" fill="none" stroke="#000080" stroke-width=".2"/>
<path d="M80.9 112.6v2.4" fill="none" stroke="#000080" stroke-width=".25"/>
<circle cx="80.9" cy="112.6" r=".48" fill="#000080"/>
<circle cx="80.9" cy="112.6" r=".48" fill="none" stroke="#000080" stroke-width=".2"/>
<path d="M176.6 160.4v2.4" fill="none" stroke="#000080" stroke-width=".25"/>
<circle cx="176.6" cy="162.8" r=".48" fill="#000080"/>
<circle cx="176.6" cy="162.8" r=".48" fill="none" stroke="#000080" stroke-width=".2"/>
<path d="M176.6 148.4v2.4" fill="none" stroke="#000080" stroke-width=".25"/>
<circle cx="176.6" cy="148.4" r=".48" fill="#000080"/>
<circle cx="176.6" cy="148.4" r=".48" fill="none" stroke="#000080" stroke-width=".2"/>
<path d="M90.5 112.6v2.4" fill="none" stroke="#000080" stroke-width=".25"/>
<circle cx="90.5" cy="112.6" r=".48" fill="#000080"/>
<circle cx="90.5" cy="112.6" r=".48" fill="none" stroke="#000080" stroke-width=".2"/>
<path d="M80.9 124.5v2.4M90.5 124.5v2.4M100.1 124.5v2.4M76.2 155.6h-12v19.1h-28.7" fill="none" stroke="#000080" stroke-width=".25"/>
<circle cx="37.9" cy="174.7" r=".48" fill="#000080"/>
<circle cx="37.9" cy="174.7" r=".48" fill="none" stroke="#000080" stroke-width=".2"/>
<circle cx="42.7" cy="174.7" r=".48" fill="#000080"/>
<circle cx="42.7" cy="174.7" r=".48" fill="none" stroke="#000080" stroke-width=".2"/>
<path d="M76.2 158h-9.6v19.1h-31.1" fill="none" stroke="#000080" stroke-width=".25"/>
<circle cx="37.9" cy="177.1" r=".48" fill="#000080"/>
<circle cx="37.9" cy="177.1" r=".48" fill="none" stroke="#000080" stroke-width=".2"/>
<circle cx="47.5" cy="177.1" r=".48" fill="#000080"/>
<circle cx="47.5" cy="177.1" r=".48" fill="none" stroke="#000080" stroke-width=".2"/>
<path d="M76.2 150.8h-19.2v2.4" fill="none" stroke="#000080" stroke-width=".25"/>
<circle cx="57" cy="150.8" r=".48" fill="#000080"/>
<circle cx="57" cy="150.8" r=".48" fill="none" stroke="#000080" stroke-width=".2"/>
<path d="M35.5 150.8h21.5" fill="none" stroke="#000080" stroke-width=".25"/>
<circle cx="57" cy="150.8" r=".48" fill="#000080"/>
<circle cx="57" cy="150.8" r=".48" fill="none" stroke="#000080" stroke-width=".2"/>
<circle cx="37.9" cy="150.8" r=".48" fill="#000080"/>
<circle cx="37.9" cy="150.8" r=".48" fill="none" stroke="#000080" stroke-width=".2"/>
<path d="M57 162.8v2.4M109.6 170v2.3h4.8v-2.3" fill="none" stroke="#000080" stroke-width=".25"/>
<circle cx="112" cy="172.3" r=".48" fill="#000080"/>
<circle cx="112" cy="172.3" r=".48" fill="none" stroke="#000080" stroke-width=".2"/>
<path d="M112 172.3v2.4" fill="none" stroke="#000080" stroke-width=".25"/>
<circle cx="112" cy="172.3" r=".48" fill="#000080"/>
<circle cx="112" cy="172.3" r=".48" fill="none" stroke="#000080" stroke-width=".2"/>
<path d="M109.6 155.6v4.8" fill="none" stroke="#000080" stroke-width=".25"/>
<circle cx="109.6" cy="155.6" r=".48" fill="#000080"/>
<circle cx="109.6" cy="155.6" r=".48" fill="none" stroke="#000080" stroke-width=".2"/>
<path d="M114.4 158v2.4" fill="none" stroke="#000080" stroke-width=".25"/>
<circle cx="114.4" cy="158" r=".48" fill="#000080"/>
<circle cx="114.4" cy="158" r=".48" fill="none" stroke="#000080" stroke-width=".2"/>
<path d="M76.2 112.6h23.9v2.4" fill="none" stroke="#000080" stroke-width=".25"/>
<circle cx="80.9" cy="112.6" r=".48" fill="#000080"/>
<circle cx="80.9" cy="112.6" r=".48" fill="none" stroke="#000080" stroke-width=".2"/>
<circle cx="90.5" cy="112.6" r=".48" fill="#000080"/>
<circle cx="90.5" cy="112.6" r=".48" fill="none" stroke="#000080" stroke-width=".2"/>
<circle cx="95.3" cy="112.6" r=".48" fill="#000080"/>
<circle cx="95.3" cy="112.6" r=".48" fill="none" stroke="#000080" stroke-width=".2"/>
<circle cx="100.1" cy="112.6" r=".48" fill="#000080"/>
<circle cx="100.1" cy="112.6" r=".48" fill="none" stroke="#000080" stroke-width=".2"/>
<path d="M104.8 110.2v2.4h-4.7" fill="none" stroke="#000080" stroke-width=".25"/>
<circle cx="100.1" cy="112.6" r=".48" fill="#000080"/>
<circle cx="100.1" cy="112.6" r=".48" fill="none" stroke="#000080" stroke-width=".2"/>
<path d="M71.4 146.1v2.3h4.8M107.2 158h33.5" fill="none" stroke="#000080" stroke-width=".25"/>
<circle cx="114.4" cy="158" r=".48" fill="#000080"/>
<circle cx="114.4" cy="158" r=".48" fill="none" stroke="#000080" stroke-width=".2"/>
<circle cx="135.9" cy="158" r=".48" fill="#000080"/>
<circle cx="135.9" cy="158" r=".48" fill="none" stroke="#000080" stroke-width=".2"/>
<path d="M107.2 155.6h43.1" fill="none" stroke="#000080" stroke-width=".25"/>
<circle cx="109.6" cy="155.6" r=".48" fill="#000080"/>
<circle cx="109.6" cy="155.6" r=".48" fill="none" stroke="#000080" stroke-width=".2"/>
<circle cx="138.3" cy="155.6" r=".48" fill="#000080"/>
<circle cx="138.3" cy="155.6" r=".48" fill="none" stroke="#000080" stroke-width=".2"/>
<path d="M181.4 150.8v12h-9.6v-4.8h-21.5" fill="none" stroke="#000080" stroke-width=".25"/>
<circle cx="176.6" cy="162.8" r=".48" fill="#000080"/>
<circle cx="176.6" cy="162.8" r=".48" fill="none" stroke="#000080" stroke-width=".2"/>
<path d="M181.4 148.4h-9.6v7.2h-12" fill="none" stroke="#000080" stroke-width=".25"/>
<circle cx="176.6" cy="148.4" r=".48" fill="#000080"/>
<circle cx="176.6" cy="148.4" r=".48" fill="none" stroke="#000080" stroke-width=".2"/>
<path d="M133.5 138.9h2.4v19.1" fill="none" stroke="#000080" stroke-width=".25"/>
<circle cx="135.9" cy="158" r=".48" fill="#000080"/>
<circle cx="135.9" cy="158" r=".48" fill="none" stroke="#000080" stroke-width=".2"/>
<path d="M140.7 138.9h-2.4v16.7" fill="none" stroke="#000080" stroke-width=".25"/>
<circle cx="138.3" cy="155.6" r=".48" fill="#000080"/>
<circle cx="138.3" cy="155.6" r=".48" fill="none" stroke="#000080" stroke-width=".2"/>
<circle cx="112" cy="33.7" r=".48" fill="#000080"/>
<circle cx="112" cy="33.7" r=".48" fill="none" stroke="#000080" stroke-width=".2"/>
<path d="M112 31.3v2.4" fill="none" stroke="#000" stroke-width=".25"/>
<circle cx="112" cy="33.7" r=".48" fill="#000080"/>
<circle cx="112" cy="33.7" r=".48" fill="none" stroke="#000080" stroke-width=".2"/>
<circle cx="112" cy="30.1" r="1.2" fill="none" stroke="#000" stroke-width=".25"/>
<circle cx="95.3" cy="112.6" r=".48" fill="#000080"/>
<circle cx="95.3" cy="112.6" r=".48" fill="none" stroke="#000080" stroke-width=".2"/>
<path d="M95.3 110.2v2.4" fill="none" stroke="#000" stroke-width=".25"/>
<circle cx="95.3" cy="112.6" r=".48" fill="#000080"/>
<circle cx="95.3" cy="112.6" r=".48" fill="none" stroke="#000080" stroke-width=".2"/>
<g fill="none" stroke="#000" stroke-width=".25">
<path d="M135.9 67.2v2.4M140.7 67.2v2.4M145.5 67.2v2.4M135.9 83.9v2.4M140.7 83.9v2.4"/>
<circle cx="135.9" cy="66" r="1.2"/>
<circle cx="140.7" cy="66" r="1.19"/>
<circle cx="145.5" cy="66" r="1.19"/>
<circle cx="135.9" cy="87.5" r="1.2"/>
<circle cx="140.7" cy="87.5" r="1.19"/>
<circle cx="95.3" cy="109" r="1.2"/>
</g>
<path d="M145.5 69.6v2.4" fill="none" stroke="#000080" stroke-width=".25"/>
<circle cx="145.5" cy="72" r=".48" fill="#000080"/>
<circle cx="145.5" cy="72" r=".48" fill="none" stroke="#000080" stroke-width=".2"/>
<path d="M140.7 69.6v4.8" fill="none" stroke="#000080" stroke-width=".25"/>
<circle cx="140.7" cy="74.4" r=".48" fill="#000080"/>
<circle cx="140.7" cy="74.4" r=".48" fill="none" stroke="#000080" stroke-width=".2"/>
<path d="M135.9 69.6v7.1" fill="none" stroke="#000080" stroke-width=".25"/>
<circle cx="135.9" cy="76.7" r=".48" fill="#000080"/>
<circle cx="135.9" cy="76.7" r=".48" fill="none" stroke="#000080" stroke-width=".2"/>
<path d="M140.7 79.1v4.8" fill="none" stroke="#000080" stroke-width=".25"/>
<circle cx="140.7" cy="79.1" r=".48" fill="#000080"/>
<circle cx="140.7" cy="79.1" r=".48" fill="none" stroke="#000080" stroke-width=".2"/>
<path d="M135.9 81.5v2.4" fill="none" stroke="#000080" stroke-width=".25"/>
<circle cx="135.9" cy="81.5" r=".48" fill="#000080"/>
<circle cx="135.9" cy="81.5" r=".48" fill="none" stroke="#000080" stroke-width=".2"/>
<path d="M155 99.5h10.8l1.2 1.1-1.2 1.2h-10.8z" fill-rule="evenodd" fill="#ffff80"/>
<path d="M155 99.5h10.8l1.2 1.1-1.2 1.2h-10.8z" fill="none" stroke="#800000" stroke-width=".2"/>
<path d="M155 89.9h10.8l1.2 1.2-1.2 1.2h-10.8z" fill-rule="evenodd" fill="#ffff80"/>
<path d="M155 89.9h10.8l1.2 1.2-1.2 1.2h-10.8z" fill="none" stroke="#800000" stroke-width=".2"/>
<path d="M155 113.8h10.8l1.2 1.2-1.2 1.2h-10.8z" fill-rule="evenodd" fill="#ffff80"/>
<path d="M155 113.8h10.8l1.2 1.2-1.2 1.2h-10.8z" fill="none" stroke="#800000" stroke-width=".2"/>
<path d="M155 104.2h10.8l1.2 1.2-1.2 1.2h-10.8z" fill-rule="evenodd" fill="#ffff80"/>
<path d="M155 104.2h10.8l1.2 1.2-1.2 1.2h-10.8z" fill="none" stroke="#800000" stroke-width=".2"/>
<path d="M155 128.1h10.8l1.2 1.2-1.2 1.2h-10.8z" fill-rule="evenodd" fill="#ffff80"/>
<path d="M155 128.1h10.8l1.2 1.2-1.2 1.2h-10.8z" fill="none" stroke="#800000" stroke-width=".2"/>
<path d="M155 118.6h10.8l1.2 1.2-1.2 1.2h-10.8z" fill-rule="evenodd" fill="#ffff80"/>
<path d="M155 118.6h10.8l1.2 1.2-1.2 1.2h-10.8z" fill="none" stroke="#800000" stroke-width=".2"/>
<path d="M155 142.5h10.8l1.2 1.2-1.2 1.2h-10.8z" fill-rule="evenodd" fill="#ffff80"/>
<path d="M155 142.5h10.8l1.2 1.2-1.2 1.2h-10.8z" fill="none" stroke="#800000" stroke-width=".2"/>
<path d="M155 132.9h10.8l1.2 1.2-1.2 1.2h-10.8z" fill-rule="evenodd" fill="#ffff80"/>
<path d="M155 132.9h10.8l1.2 1.2-1.2 1.2h-10.8z" fill="none" stroke="#800000" stroke-width=".2"/>
<use href="#words"/>
</svg>
